VERSION 5.8 ;
BUSBITCHARS "[]" ;
DIVIDERCHAR "/" ;
UNITS
    DATABASE MICRONS 1000 ;
END UNITS

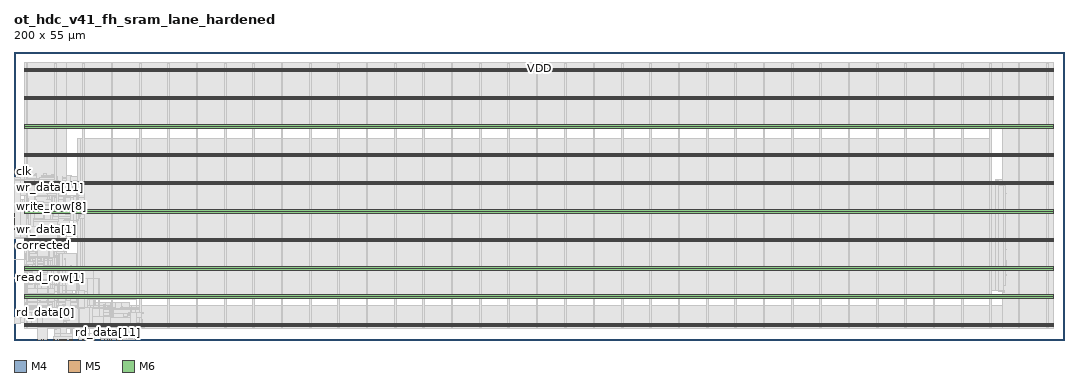
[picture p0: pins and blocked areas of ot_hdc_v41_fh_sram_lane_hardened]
MACRO ot_hdc_v41_fh_sram_lane_hardened
  FOREIGN ot_hdc_v41_fh_sram_lane_hardened 0 0 ;
  CLASS BLOCK ;
  SIZE 200 BY 55 ;
  PIN bank_id[0]
    DIRECTION INPUT ;
    USE SIGNAL ;
    PORT
      LAYER M4 ;
        RECT  0 26.016 0.084 26.04 ;
    END
  END bank_id[0]
  PIN bank_id[1]
    DIRECTION INPUT ;
    USE SIGNAL ;
    PORT
      LAYER M4 ;
        RECT  0 22.176 0.084 22.2 ;
    END
  END bank_id[1]
  PIN bank_id[2]
    DIRECTION INPUT ;
    USE SIGNAL ;
    PORT
      LAYER M4 ;
        RECT  0 22.272 0.084 22.296 ;
    END
  END bank_id[2]
  PIN bank_id[3]
    DIRECTION INPUT ;
    USE SIGNAL ;
    PORT
      LAYER M4 ;
        RECT  0 23.616 0.084 23.64 ;
    END
  END bank_id[3]
  PIN bank_id[4]
    DIRECTION INPUT ;
    USE SIGNAL ;
    PORT
      LAYER M4 ;
        RECT  0 23.712 0.084 23.736 ;
    END
  END bank_id[4]
  PIN bank_id[5]
    DIRECTION INPUT ;
    USE SIGNAL ;
    PORT
      LAYER M4 ;
        RECT  0 24.96 0.084 24.984 ;
    END
  END bank_id[5]
  PIN clk
    DIRECTION INPUT ;
    USE SIGNAL ;
    PORT
      LAYER M4 ;
        RECT  0 30.528 0.084 30.552 ;
    END
  END clk
  PIN corrected
    DIRECTION OUTPUT ;
    USE SIGNAL ;
    PORT
      LAYER M4 ;
        RECT  0 19.488 0.084 19.512 ;
    END
  END corrected
  PIN poisoned
    DIRECTION OUTPUT ;
    USE SIGNAL ;
    PORT
      LAYER M4 ;
        RECT  0 19.68 0.084 19.704 ;
    END
  END poisoned
  PIN rd_data[0]
    DIRECTION OUTPUT ;
    USE SIGNAL ;
    PORT
      LAYER M4 ;
        RECT  0 3.648 0.084 3.672 ;
    END
  END rd_data[0]
  PIN rd_data[10]
    DIRECTION OUTPUT ;
    USE SIGNAL ;
    PORT
      LAYER M5 ;
        RECT  6.432 0 6.456 0.084 ;
    END
  END rd_data[10]
  PIN rd_data[11]
    DIRECTION OUTPUT ;
    USE SIGNAL ;
    PORT
      LAYER M5 ;
        RECT  17.856 0 17.88 0.084 ;
    END
  END rd_data[11]
  PIN rd_data[12]
    DIRECTION OUTPUT ;
    USE SIGNAL ;
    PORT
      LAYER M5 ;
        RECT  17.184 0 17.208 0.084 ;
    END
  END rd_data[12]
  PIN rd_data[13]
    DIRECTION OUTPUT ;
    USE SIGNAL ;
    PORT
      LAYER M5 ;
        RECT  18.528 0 18.552 0.084 ;
    END
  END rd_data[13]
  PIN rd_data[14]
    DIRECTION OUTPUT ;
    USE SIGNAL ;
    PORT
      LAYER M5 ;
        RECT  18.144 0 18.168 0.084 ;
    END
  END rd_data[14]
  PIN rd_data[15]
    DIRECTION OUTPUT ;
    USE SIGNAL ;
    PORT
      LAYER M5 ;
        RECT  20.64 0 20.664 0.084 ;
    END
  END rd_data[15]
  PIN rd_data[16]
    DIRECTION OUTPUT ;
    USE SIGNAL ;
    PORT
      LAYER M5 ;
        RECT  20.736 0 20.76 0.084 ;
    END
  END rd_data[16]
  PIN rd_data[17]
    DIRECTION OUTPUT ;
    USE SIGNAL ;
    PORT
      LAYER M5 ;
        RECT  19.968 0 19.992 0.084 ;
    END
  END rd_data[17]
  PIN rd_data[18]
    DIRECTION OUTPUT ;
    USE SIGNAL ;
    PORT
      LAYER M5 ;
        RECT  19.488 0 19.512 0.084 ;
    END
  END rd_data[18]
  PIN rd_data[19]
    DIRECTION OUTPUT ;
    USE SIGNAL ;
    PORT
      LAYER M5 ;
        RECT  20.16 0 20.184 0.084 ;
    END
  END rd_data[19]
  PIN rd_data[1]
    DIRECTION OUTPUT ;
    USE SIGNAL ;
    PORT
      LAYER M5 ;
        RECT  4.416 0 4.44 0.084 ;
    END
  END rd_data[1]
  PIN rd_data[20]
    DIRECTION OUTPUT ;
    USE SIGNAL ;
    PORT
      LAYER M5 ;
        RECT  20.064 0 20.088 0.084 ;
    END
  END rd_data[20]
  PIN rd_data[21]
    DIRECTION OUTPUT ;
    USE SIGNAL ;
    PORT
      LAYER M5 ;
        RECT  16.512 0 16.536 0.084 ;
    END
  END rd_data[21]
  PIN rd_data[22]
    DIRECTION OUTPUT ;
    USE SIGNAL ;
    PORT
      LAYER M5 ;
        RECT  16.416 0 16.44 0.084 ;
    END
  END rd_data[22]
  PIN rd_data[23]
    DIRECTION OUTPUT ;
    USE SIGNAL ;
    PORT
      LAYER M5 ;
        RECT  13.056 0 13.08 0.084 ;
    END
  END rd_data[23]
  PIN rd_data[24]
    DIRECTION OUTPUT ;
    USE SIGNAL ;
    PORT
      LAYER M5 ;
        RECT  14.304 0 14.328 0.084 ;
    END
  END rd_data[24]
  PIN rd_data[25]
    DIRECTION OUTPUT ;
    USE SIGNAL ;
    PORT
      LAYER M5 ;
        RECT  15.36 0 15.384 0.084 ;
    END
  END rd_data[25]
  PIN rd_data[26]
    DIRECTION OUTPUT ;
    USE SIGNAL ;
    PORT
      LAYER M5 ;
        RECT  12.192 0 12.216 0.084 ;
    END
  END rd_data[26]
  PIN rd_data[27]
    DIRECTION OUTPUT ;
    USE SIGNAL ;
    PORT
      LAYER M5 ;
        RECT  13.152 0 13.176 0.084 ;
    END
  END rd_data[27]
  PIN rd_data[28]
    DIRECTION OUTPUT ;
    USE SIGNAL ;
    PORT
      LAYER M5 ;
        RECT  14.88 0 14.904 0.084 ;
    END
  END rd_data[28]
  PIN rd_data[29]
    DIRECTION OUTPUT ;
    USE SIGNAL ;
    PORT
      LAYER M5 ;
        RECT  10.656 0 10.68 0.084 ;
    END
  END rd_data[29]
  PIN rd_data[2]
    DIRECTION OUTPUT ;
    USE SIGNAL ;
    PORT
      LAYER M4 ;
        RECT  0 3.072 0.084 3.096 ;
    END
  END rd_data[2]
  PIN rd_data[30]
    DIRECTION OUTPUT ;
    USE SIGNAL ;
    PORT
      LAYER M5 ;
        RECT  11.04 0 11.064 0.084 ;
    END
  END rd_data[30]
  PIN rd_data[31]
    DIRECTION OUTPUT ;
    USE SIGNAL ;
    PORT
      LAYER M4 ;
        RECT  0 4.224 0.084 4.248 ;
    END
  END rd_data[31]
  PIN rd_data[3]
    DIRECTION OUTPUT ;
    USE SIGNAL ;
    PORT
      LAYER M5 ;
        RECT  7.488 0 7.512 0.084 ;
    END
  END rd_data[3]
  PIN rd_data[4]
    DIRECTION OUTPUT ;
    USE SIGNAL ;
    PORT
      LAYER M5 ;
        RECT  7.776 0 7.8 0.084 ;
    END
  END rd_data[4]
  PIN rd_data[5]
    DIRECTION OUTPUT ;
    USE SIGNAL ;
    PORT
      LAYER M5 ;
        RECT  8.928 0 8.952 0.084 ;
    END
  END rd_data[5]
  PIN rd_data[6]
    DIRECTION OUTPUT ;
    USE SIGNAL ;
    PORT
      LAYER M5 ;
        RECT  9.888 0 9.912 0.084 ;
    END
  END rd_data[6]
  PIN rd_data[7]
    DIRECTION OUTPUT ;
    USE SIGNAL ;
    PORT
      LAYER M5 ;
        RECT  8.736 0 8.76 0.084 ;
    END
  END rd_data[7]
  PIN rd_data[8]
    DIRECTION OUTPUT ;
    USE SIGNAL ;
    PORT
      LAYER M5 ;
        RECT  5.664 0 5.688 0.084 ;
    END
  END rd_data[8]
  PIN rd_data[9]
    DIRECTION OUTPUT ;
    USE SIGNAL ;
    PORT
      LAYER M5 ;
        RECT  5.184 0 5.208 0.084 ;
    END
  END rd_data[9]
  PIN rd_valid
    DIRECTION OUTPUT ;
    USE SIGNAL ;
    PORT
      LAYER M4 ;
        RECT  0 19.872 0.084 19.896 ;
    END
  END rd_valid
  PIN read_ok
    DIRECTION INPUT ;
    USE SIGNAL ;
    PORT
      LAYER M5 ;
        RECT  8.832 0 8.856 0.084 ;
    END
  END read_ok
  PIN read_row[0]
    DIRECTION INPUT ;
    USE SIGNAL ;
    PORT
      LAYER M5 ;
        RECT  9.024 0 9.048 0.084 ;
    END
  END read_row[0]
  PIN read_row[1]
    DIRECTION INPUT ;
    USE SIGNAL ;
    PORT
      LAYER M4 ;
        RECT  0 11.904 0.084 11.928 ;
    END
  END read_row[1]
  PIN read_row[2]
    DIRECTION INPUT ;
    USE SIGNAL ;
    PORT
      LAYER M5 ;
        RECT  8.352 0 8.376 0.084 ;
    END
  END read_row[2]
  PIN read_row[3]
    DIRECTION INPUT ;
    USE SIGNAL ;
    PORT
      LAYER M4 ;
        RECT  0 15.36 0.084 15.384 ;
    END
  END read_row[3]
  PIN read_row[4]
    DIRECTION INPUT ;
    USE SIGNAL ;
    PORT
      LAYER M5 ;
        RECT  9.12 0 9.144 0.084 ;
    END
  END read_row[4]
  PIN read_row[5]
    DIRECTION INPUT ;
    USE SIGNAL ;
    PORT
      LAYER M5 ;
        RECT  9.216 0 9.24 0.084 ;
    END
  END read_row[5]
  PIN read_row[6]
    DIRECTION INPUT ;
    USE SIGNAL ;
    PORT
      LAYER M5 ;
        RECT  9.312 0 9.336 0.084 ;
    END
  END read_row[6]
  PIN read_row[7]
    DIRECTION INPUT ;
    USE SIGNAL ;
    PORT
      LAYER M5 ;
        RECT  9.408 0 9.432 0.084 ;
    END
  END read_row[7]
  PIN read_row[8]
    DIRECTION INPUT ;
    USE SIGNAL ;
    PORT
      LAYER M5 ;
        RECT  9.504 0 9.528 0.084 ;
    END
  END read_row[8]
  PIN rst_n
    DIRECTION INPUT ;
    USE SIGNAL ;
    PORT
      LAYER M4 ;
        RECT  0 19.584 0.084 19.608 ;
    END
  END rst_n
  PIN wr_committed
    DIRECTION OUTPUT ;
    USE SIGNAL ;
    PORT
      LAYER M4 ;
        RECT  0 19.968 0.084 19.992 ;
    END
  END wr_committed
  PIN wr_data[0]
    DIRECTION INPUT ;
    USE SIGNAL ;
    PORT
      LAYER M4 ;
        RECT  0 24.384 0.084 24.408 ;
    END
  END wr_data[0]
  PIN wr_data[10]
    DIRECTION INPUT ;
    USE SIGNAL ;
    PORT
      LAYER M4 ;
        RECT  0 20.64 0.084 20.664 ;
    END
  END wr_data[10]
  PIN wr_data[11]
    DIRECTION INPUT ;
    USE SIGNAL ;
    PORT
      LAYER M4 ;
        RECT  0 28.992 0.084 29.016 ;
    END
  END wr_data[11]
  PIN wr_data[12]
    DIRECTION INPUT ;
    USE SIGNAL ;
    PORT
      LAYER M4 ;
        RECT  0 23.04 0.084 23.064 ;
    END
  END wr_data[12]
  PIN wr_data[13]
    DIRECTION INPUT ;
    USE SIGNAL ;
    PORT
      LAYER M4 ;
        RECT  0 24 0.084 24.024 ;
    END
  END wr_data[13]
  PIN wr_data[14]
    DIRECTION INPUT ;
    USE SIGNAL ;
    PORT
      LAYER M4 ;
        RECT  0 30.144 0.084 30.168 ;
    END
  END wr_data[14]
  PIN wr_data[15]
    DIRECTION INPUT ;
    USE SIGNAL ;
    PORT
      LAYER M4 ;
        RECT  0 30.72 0.084 30.744 ;
    END
  END wr_data[15]
  PIN wr_data[16]
    DIRECTION INPUT ;
    USE SIGNAL ;
    PORT
      LAYER M4 ;
        RECT  0 30.624 0.084 30.648 ;
    END
  END wr_data[16]
  PIN wr_data[17]
    DIRECTION INPUT ;
    USE SIGNAL ;
    PORT
      LAYER M4 ;
        RECT  0 29.664 0.084 29.688 ;
    END
  END wr_data[17]
  PIN wr_data[18]
    DIRECTION INPUT ;
    USE SIGNAL ;
    PORT
      LAYER M4 ;
        RECT  0 30.912 0.084 30.936 ;
    END
  END wr_data[18]
  PIN wr_data[19]
    DIRECTION INPUT ;
    USE SIGNAL ;
    PORT
      LAYER M4 ;
        RECT  0 30.816 0.084 30.84 ;
    END
  END wr_data[19]
  PIN wr_data[1]
    DIRECTION INPUT ;
    USE SIGNAL ;
    PORT
      LAYER M4 ;
        RECT  0 21.12 0.084 21.144 ;
    END
  END wr_data[1]
  PIN wr_data[20]
    DIRECTION INPUT ;
    USE SIGNAL ;
    PORT
      LAYER M4 ;
        RECT  0 31.008 0.084 31.032 ;
    END
  END wr_data[20]
  PIN wr_data[21]
    DIRECTION INPUT ;
    USE SIGNAL ;
    PORT
      LAYER M4 ;
        RECT  0 30.24 0.084 30.264 ;
    END
  END wr_data[21]
  PIN wr_data[22]
    DIRECTION INPUT ;
    USE SIGNAL ;
    PORT
      LAYER M4 ;
        RECT  0 29.856 0.084 29.88 ;
    END
  END wr_data[22]
  PIN wr_data[23]
    DIRECTION INPUT ;
    USE SIGNAL ;
    PORT
      LAYER M4 ;
        RECT  0 29.76 0.084 29.784 ;
    END
  END wr_data[23]
  PIN wr_data[24]
    DIRECTION INPUT ;
    USE SIGNAL ;
    PORT
      LAYER M4 ;
        RECT  0 28.128 0.084 28.152 ;
    END
  END wr_data[24]
  PIN wr_data[25]
    DIRECTION INPUT ;
    USE SIGNAL ;
    PORT
      LAYER M4 ;
        RECT  0 26.112 0.084 26.136 ;
    END
  END wr_data[25]
  PIN wr_data[26]
    DIRECTION INPUT ;
    USE SIGNAL ;
    PORT
      LAYER M4 ;
        RECT  0 23.808 0.084 23.832 ;
    END
  END wr_data[26]
  PIN wr_data[27]
    DIRECTION INPUT ;
    USE SIGNAL ;
    PORT
      LAYER M4 ;
        RECT  0 29.088 0.084 29.112 ;
    END
  END wr_data[27]
  PIN wr_data[28]
    DIRECTION INPUT ;
    USE SIGNAL ;
    PORT
      LAYER M4 ;
        RECT  0 23.328 0.084 23.352 ;
    END
  END wr_data[28]
  PIN wr_data[29]
    DIRECTION INPUT ;
    USE SIGNAL ;
    PORT
      LAYER M4 ;
        RECT  0 24.768 0.084 24.792 ;
    END
  END wr_data[29]
  PIN wr_data[2]
    DIRECTION INPUT ;
    USE SIGNAL ;
    PORT
      LAYER M4 ;
        RECT  0 21.6 0.084 21.624 ;
    END
  END wr_data[2]
  PIN wr_data[30]
    DIRECTION INPUT ;
    USE SIGNAL ;
    PORT
      LAYER M4 ;
        RECT  0 26.784 0.084 26.808 ;
    END
  END wr_data[30]
  PIN wr_data[31]
    DIRECTION INPUT ;
    USE SIGNAL ;
    PORT
      LAYER M4 ;
        RECT  0 28.32 0.084 28.344 ;
    END
  END wr_data[31]
  PIN wr_data[3]
    DIRECTION INPUT ;
    USE SIGNAL ;
    PORT
      LAYER M4 ;
        RECT  0 23.136 0.084 23.16 ;
    END
  END wr_data[3]
  PIN wr_data[4]
    DIRECTION INPUT ;
    USE SIGNAL ;
    PORT
      LAYER M4 ;
        RECT  0 20.064 0.084 20.088 ;
    END
  END wr_data[4]
  PIN wr_data[5]
    DIRECTION INPUT ;
    USE SIGNAL ;
    PORT
      LAYER M4 ;
        RECT  0 20.256 0.084 20.28 ;
    END
  END wr_data[5]
  PIN wr_data[6]
    DIRECTION INPUT ;
    USE SIGNAL ;
    PORT
      LAYER M4 ;
        RECT  0 20.832 0.084 20.856 ;
    END
  END wr_data[6]
  PIN wr_data[7]
    DIRECTION INPUT ;
    USE SIGNAL ;
    PORT
      LAYER M4 ;
        RECT  0 20.16 0.084 20.184 ;
    END
  END wr_data[7]
  PIN wr_data[8]
    DIRECTION INPUT ;
    USE SIGNAL ;
    PORT
      LAYER M4 ;
        RECT  0 20.544 0.084 20.568 ;
    END
  END wr_data[8]
  PIN wr_data[9]
    DIRECTION INPUT ;
    USE SIGNAL ;
    PORT
      LAYER M4 ;
        RECT  0 20.448 0.084 20.472 ;
    END
  END wr_data[9]
  PIN write_ok
    DIRECTION INPUT ;
    USE SIGNAL ;
    PORT
      LAYER M4 ;
        RECT  0 19.776 0.084 19.8 ;
    END
  END write_ok
  PIN write_row[0]
    DIRECTION INPUT ;
    USE SIGNAL ;
    PORT
      LAYER M4 ;
        RECT  0 23.904 0.084 23.928 ;
    END
  END write_row[0]
  PIN write_row[1]
    DIRECTION INPUT ;
    USE SIGNAL ;
    PORT
      LAYER M4 ;
        RECT  0 24.576 0.084 24.6 ;
    END
  END write_row[1]
  PIN write_row[2]
    DIRECTION INPUT ;
    USE SIGNAL ;
    PORT
      LAYER M4 ;
        RECT  0 27.456 0.084 27.48 ;
    END
  END write_row[2]
  PIN write_row[3]
    DIRECTION INPUT ;
    USE SIGNAL ;
    PORT
      LAYER M4 ;
        RECT  0 20.736 0.084 20.76 ;
    END
  END write_row[3]
  PIN write_row[4]
    DIRECTION INPUT ;
    USE SIGNAL ;
    PORT
      LAYER M4 ;
        RECT  0 20.352 0.084 20.376 ;
    END
  END write_row[4]
  PIN write_row[5]
    DIRECTION INPUT ;
    USE SIGNAL ;
    PORT
      LAYER M4 ;
        RECT  0 22.08 0.084 22.104 ;
    END
  END write_row[5]
  PIN write_row[6]
    DIRECTION INPUT ;
    USE SIGNAL ;
    PORT
      LAYER M4 ;
        RECT  0 22.656 0.084 22.68 ;
    END
  END write_row[6]
  PIN write_row[7]
    DIRECTION INPUT ;
    USE SIGNAL ;
    PORT
      LAYER M4 ;
        RECT  0 26.208 0.084 26.232 ;
    END
  END write_row[7]
  PIN write_row[8]
    DIRECTION INPUT ;
    USE SIGNAL ;
    PORT
      LAYER M4 ;
        RECT  0 25.344 0.084 25.368 ;
    END
  END write_row[8]
  PIN VDD
    DIRECTION INOUT ;
    USE POWER ;
    PORT
      LAYER M6 ;
        RECT  2.052 51.513 197.964 51.801 ;
        RECT  2.052 46.113 197.964 46.401 ;
        RECT  2.052 40.713 197.964 41.001 ;
        RECT  2.052 35.313 197.964 35.601 ;
        RECT  2.052 29.913 197.964 30.201 ;
        RECT  2.052 24.513 197.964 24.801 ;
        RECT  2.052 19.113 197.964 19.401 ;
        RECT  2.052 13.713 197.964 14.001 ;
        RECT  2.052 8.313 197.964 8.601 ;
        RECT  2.052 2.913 197.964 3.201 ;
    END
  END VDD
  PIN VSS
    DIRECTION INOUT ;
    USE GROUND ;
    PORT
      LAYER M6 ;
        RECT  2.052 51.129 197.964 51.417 ;
        RECT  2.052 45.729 197.964 46.017 ;
        RECT  2.052 40.329 197.964 40.617 ;
        RECT  2.052 34.929 197.964 35.217 ;
        RECT  2.052 29.529 197.964 29.817 ;
        RECT  2.052 24.129 197.964 24.417 ;
        RECT  2.052 18.729 197.964 19.017 ;
        RECT  2.052 13.329 197.964 13.617 ;
        RECT  2.052 7.929 197.964 8.217 ;
        RECT  2.052 2.529 197.964 2.817 ;
    END
  END VSS
  OBS
    LAYER LVTN ;
     RECT  4.698 2.7 5.076 2.835 ;
     RECT  6.048 2.7 7.992 2.835 ;
     RECT  9.45 2.7 9.828 2.835 ;
     RECT  10.962 2.7 11.34 2.835 ;
     RECT  12.096 2.7 12.69 2.835 ;
     RECT  14.472 2.7 15.066 2.835 ;
     RECT  15.714 2.7 16.092 2.835 ;
     RECT  16.524 2.7 16.956 2.835 ;
     RECT  17.442 2.7 18.414 2.835 ;
     RECT  19.278 2.7 19.71 2.835 ;
     RECT  20.79 2.7 21.168 2.835 ;
     RECT  22.626 2.7 23.328 2.835 ;
     RECT  23.868 2.7 27 2.835 ;
     RECT  8.046 3.105 8.424 3.24 ;
     RECT  11.934 3.105 12.312 3.24 ;
     RECT  12.96 3.105 14.094 3.24 ;
     RECT  14.958 3.105 15.498 3.24 ;
     RECT  19.494 3.105 19.872 3.24 ;
     RECT  5.076 3.24 6.48 3.375 ;
     RECT  8.046 3.24 9.234 3.375 ;
     RECT  10.8 3.24 11.178 3.375 ;
     RECT  11.61 3.24 11.988 3.375 ;
     RECT  16.146 3.24 19.332 3.375 ;
     RECT  20.628 3.24 22.626 3.375 ;
     RECT  23.274 3.24 24.084 3.375 ;
     RECT  4.698 3.645 5.562 3.78 ;
     RECT  6.966 3.645 8.694 3.78 ;
     RECT  10.098 3.645 10.422 3.78 ;
     RECT  18.198 3.645 20.088 3.78 ;
     RECT  20.466 3.645 21.978 3.78 ;
     RECT  22.14 3.645 23.274 3.78 ;
     RECT  3.672 3.78 5.022 3.915 ;
     RECT  5.292 3.78 5.616 3.915 ;
     RECT  11.07 3.78 11.394 3.915 ;
     RECT  12.474 3.78 15.174 3.915 ;
     RECT  19.656 3.78 20.25 3.915 ;
     RECT  23.76 3.78 27 3.915 ;
     RECT  10.962 4.185 11.61 4.32 ;
     RECT  18.63 4.185 18.954 4.32 ;
     RECT  21.168 4.185 22.086 4.32 ;
     RECT  3.078 4.32 3.78 4.455 ;
     RECT  16.092 4.32 16.74 4.455 ;
     RECT  18.468 4.32 19.44 4.455 ;
     RECT  23.598 4.32 27 4.455 ;
     RECT  4.212 4.725 5.67 4.86 ;
     RECT  9.18 4.725 9.504 4.86 ;
     RECT  3.132 5.265 3.51 5.4 ;
     RECT  14.85 5.4 16.362 5.535 ;
     RECT  3.348 16.605 4.158 16.74 ;
     RECT  2.7 16.74 3.402 16.875 ;
     RECT  4.05 16.74 4.212 16.875 ;
     RECT  4.806 16.74 5.832 16.875 ;
     RECT  4.212 17.145 5.292 17.28 ;
     RECT  2.754 17.28 3.726 17.415 ;
     RECT  5.778 17.28 8.316 17.415 ;
     RECT  4.158 17.685 5.454 17.82 ;
     RECT  3.942 17.82 4.536 17.955 ;
     RECT  5.346 17.82 7.074 17.955 ;
     RECT  7.074 18.225 8.316 18.36 ;
     RECT  3.726 18.36 5.238 18.495 ;
     RECT  4.104 21.06 4.914 21.195 ;
     RECT  5.508 21.06 6.102 21.195 ;
     RECT  4.104 21.465 4.698 21.6 ;
     RECT  2.214 22.005 4.752 22.14 ;
     RECT  5.94 22.005 6.858 22.14 ;
     RECT  5.454 22.14 6.534 22.275 ;
     RECT  4.428 22.545 5.076 22.68 ;
     RECT  4.158 22.68 5.238 22.815 ;
     RECT  5.94 22.68 6.696 22.815 ;
     RECT  4.59 23.085 5.238 23.22 ;
     RECT  5.832 23.085 6.966 23.22 ;
     RECT  2.484 23.22 3.888 23.355 ;
     RECT  2.268 23.625 2.538 23.76 ;
     RECT  5.67 23.76 6.264 23.895 ;
     RECT  5.184 24.3 6.426 24.435 ;
     RECT  2.484 24.705 2.754 24.84 ;
     RECT  5.94 24.705 6.966 24.84 ;
     RECT  5.292 24.84 6.804 24.975 ;
     RECT  4.482 25.245 5.4 25.38 ;
     RECT  6.156 25.245 6.858 25.38 ;
     RECT  3.78 25.38 4.374 25.515 ;
     RECT  2.484 25.785 4.05 25.92 ;
     RECT  6.75 25.785 7.344 25.92 ;
     RECT  3.834 25.92 5.4 26.055 ;
     RECT  3.942 26.46 4.752 26.595 ;
     RECT  7.182 26.46 7.776 26.595 ;
     RECT  3.564 26.865 4.158 27 ;
     RECT  4.482 27 5.076 27.135 ;
     RECT  5.67 27 6.75 27.135 ;
     RECT  7.128 27.405 7.938 27.54 ;
     RECT  4.32 27.54 4.914 27.675 ;
     RECT  5.724 27.54 6.696 27.675 ;
     RECT  6.048 27.945 6.642 28.08 ;
     RECT  7.128 28.08 7.83 28.215 ;
     RECT  5.994 28.485 8.046 28.62 ;
     RECT  5.562 28.62 6.966 28.755 ;
    LAYER LVTP ;
     RECT  4.698 2.835 5.076 2.97 ;
     RECT  6.048 2.835 7.992 2.97 ;
     RECT  9.45 2.835 9.828 2.97 ;
     RECT  10.962 2.835 11.34 2.97 ;
     RECT  12.096 2.835 12.69 2.97 ;
     RECT  14.472 2.835 15.066 2.97 ;
     RECT  15.714 2.835 16.092 2.97 ;
     RECT  16.524 2.835 16.956 2.97 ;
     RECT  17.442 2.835 18.414 2.97 ;
     RECT  19.278 2.835 19.71 2.97 ;
     RECT  20.79 2.835 21.168 2.97 ;
     RECT  22.626 2.835 23.328 2.97 ;
     RECT  23.868 2.835 27 2.97 ;
     RECT  8.046 2.97 8.424 3.105 ;
     RECT  11.934 2.97 12.312 3.105 ;
     RECT  12.96 2.97 14.094 3.105 ;
     RECT  14.958 2.97 15.498 3.105 ;
     RECT  19.494 2.97 19.872 3.105 ;
     RECT  5.076 3.375 6.48 3.51 ;
     RECT  8.046 3.375 9.234 3.51 ;
     RECT  10.8 3.375 11.178 3.51 ;
     RECT  11.61 3.375 11.988 3.51 ;
     RECT  16.146 3.375 19.332 3.51 ;
     RECT  20.628 3.375 22.626 3.51 ;
     RECT  23.274 3.375 24.084 3.51 ;
     RECT  4.698 3.51 5.562 3.645 ;
     RECT  6.966 3.51 8.694 3.645 ;
     RECT  10.098 3.51 10.422 3.645 ;
     RECT  18.198 3.51 20.088 3.645 ;
     RECT  20.466 3.51 21.978 3.645 ;
     RECT  22.14 3.51 23.274 3.645 ;
     RECT  3.672 3.915 5.022 4.05 ;
     RECT  5.292 3.915 5.616 4.05 ;
     RECT  11.07 3.915 11.394 4.05 ;
     RECT  12.474 3.915 15.174 4.05 ;
     RECT  19.656 3.915 20.25 4.05 ;
     RECT  23.76 3.915 27 4.05 ;
     RECT  10.962 4.05 11.61 4.185 ;
     RECT  18.63 4.05 18.954 4.185 ;
     RECT  21.168 4.05 22.086 4.185 ;
     RECT  3.078 4.455 3.78 4.59 ;
     RECT  16.092 4.455 16.74 4.59 ;
     RECT  18.468 4.455 19.44 4.59 ;
     RECT  23.598 4.455 27 4.59 ;
     RECT  4.212 4.59 5.67 4.725 ;
     RECT  9.18 4.59 9.504 4.725 ;
     RECT  3.132 5.13 3.51 5.265 ;
     RECT  14.85 5.535 16.362 5.67 ;
     RECT  3.348 16.47 4.158 16.605 ;
     RECT  2.7 16.875 3.402 17.01 ;
     RECT  4.05 16.875 4.212 17.01 ;
     RECT  4.806 16.875 5.832 17.01 ;
     RECT  4.212 17.01 5.292 17.145 ;
     RECT  2.754 17.415 3.726 17.55 ;
     RECT  5.778 17.415 8.316 17.55 ;
     RECT  4.158 17.55 5.454 17.685 ;
     RECT  3.942 17.955 4.536 18.09 ;
     RECT  5.346 17.955 7.074 18.09 ;
     RECT  7.074 18.09 8.316 18.225 ;
     RECT  3.726 18.495 5.238 18.63 ;
     RECT  4.104 21.195 4.914 21.33 ;
     RECT  5.508 21.195 6.102 21.33 ;
     RECT  4.104 21.33 4.698 21.465 ;
     RECT  2.214 21.87 4.752 22.005 ;
     RECT  5.94 21.87 6.858 22.005 ;
     RECT  5.454 22.275 6.534 22.41 ;
     RECT  4.428 22.41 5.076 22.545 ;
     RECT  4.158 22.815 5.238 22.95 ;
     RECT  5.94 22.815 6.696 22.95 ;
     RECT  4.59 22.95 5.238 23.085 ;
     RECT  5.832 22.95 6.966 23.085 ;
     RECT  2.484 23.355 3.888 23.49 ;
     RECT  2.268 23.49 2.538 23.625 ;
     RECT  5.67 23.895 6.264 24.03 ;
     RECT  5.184 24.435 6.426 24.57 ;
     RECT  2.484 24.57 2.754 24.705 ;
     RECT  5.94 24.57 6.966 24.705 ;
     RECT  5.292 24.975 6.804 25.11 ;
     RECT  4.482 25.11 5.4 25.245 ;
     RECT  6.156 25.11 6.858 25.245 ;
     RECT  3.78 25.515 4.374 25.65 ;
     RECT  2.484 25.65 4.05 25.785 ;
     RECT  6.75 25.65 7.344 25.785 ;
     RECT  3.834 26.055 5.4 26.19 ;
     RECT  3.942 26.595 4.752 26.73 ;
     RECT  7.182 26.595 7.776 26.73 ;
     RECT  3.564 26.73 4.158 26.865 ;
     RECT  4.482 27.135 5.076 27.27 ;
     RECT  5.67 27.135 6.75 27.27 ;
     RECT  7.128 27.27 7.938 27.405 ;
     RECT  4.32 27.675 4.914 27.81 ;
     RECT  5.724 27.675 6.696 27.81 ;
     RECT  6.048 27.81 6.642 27.945 ;
     RECT  7.128 28.215 7.83 28.35 ;
     RECT  5.994 28.35 8.046 28.485 ;
     RECT  5.562 28.755 6.966 28.89 ;
    LAYER RVTN ;
     RECT  2.052 2.16 197.964 2.295 ;
     RECT  2.052 2.565 197.964 2.7 ;
     RECT  2.052 2.7 4.698 2.835 ;
     RECT  5.076 2.7 6.048 2.835 ;
     RECT  7.992 2.7 9.45 2.835 ;
     RECT  9.828 2.7 10.962 2.835 ;
     RECT  11.34 2.7 12.096 2.835 ;
     RECT  12.69 2.7 14.472 2.835 ;
     RECT  15.066 2.7 15.714 2.835 ;
     RECT  16.092 2.7 16.524 2.835 ;
     RECT  16.956 2.7 17.442 2.835 ;
     RECT  18.414 2.7 19.278 2.835 ;
     RECT  19.71 2.7 20.79 2.835 ;
     RECT  21.168 2.7 22.626 2.835 ;
     RECT  23.328 2.7 23.868 2.835 ;
     RECT  27 2.7 197.964 2.835 ;
     RECT  2.052 3.105 8.046 3.24 ;
     RECT  8.424 3.105 11.934 3.24 ;
     RECT  12.312 3.105 12.96 3.24 ;
     RECT  14.094 3.105 14.958 3.24 ;
     RECT  15.498 3.105 19.494 3.24 ;
     RECT  19.872 3.105 197.964 3.24 ;
     RECT  2.052 3.24 5.076 3.375 ;
     RECT  6.48 3.24 8.046 3.375 ;
     RECT  9.234 3.24 10.8 3.375 ;
     RECT  11.178 3.24 11.61 3.375 ;
     RECT  11.988 3.24 16.146 3.375 ;
     RECT  19.332 3.24 20.628 3.375 ;
     RECT  22.626 3.24 23.274 3.375 ;
     RECT  24.084 3.24 197.964 3.375 ;
     RECT  2.052 3.645 4.698 3.78 ;
     RECT  5.562 3.645 6.966 3.78 ;
     RECT  8.694 3.645 10.098 3.78 ;
     RECT  10.422 3.645 18.198 3.78 ;
     RECT  20.088 3.645 20.466 3.78 ;
     RECT  21.978 3.645 22.14 3.78 ;
     RECT  23.274 3.645 197.964 3.78 ;
     RECT  2.052 3.78 3.672 3.915 ;
     RECT  5.022 3.78 5.292 3.915 ;
     RECT  5.616 3.78 11.07 3.915 ;
     RECT  11.394 3.78 12.474 3.915 ;
     RECT  15.174 3.78 19.656 3.915 ;
     RECT  20.25 3.78 23.76 3.915 ;
     RECT  27 3.78 197.964 3.915 ;
     RECT  2.052 4.185 10.962 4.32 ;
     RECT  11.61 4.185 18.63 4.32 ;
     RECT  18.954 4.185 21.168 4.32 ;
     RECT  22.086 4.185 197.964 4.32 ;
     RECT  2.052 4.32 3.078 4.455 ;
     RECT  3.78 4.32 16.092 4.455 ;
     RECT  16.74 4.32 18.468 4.455 ;
     RECT  19.44 4.32 23.598 4.455 ;
     RECT  27 4.32 197.964 4.455 ;
     RECT  2.052 4.725 4.212 4.86 ;
     RECT  5.67 4.725 9.18 4.86 ;
     RECT  9.504 4.725 197.964 4.86 ;
     RECT  2.052 4.86 197.964 4.995 ;
     RECT  2.052 5.265 3.132 5.4 ;
     RECT  3.51 5.265 197.964 5.4 ;
     RECT  2.052 5.4 14.85 5.535 ;
     RECT  16.362 5.4 197.964 5.535 ;
     RECT  2.052 5.805 197.964 6.075 ;
     RECT  2.052 6.345 197.964 6.48 ;
     RECT  2.052 6.48 10.044 6.615 ;
     RECT  188.244 6.48 197.964 6.615 ;
     RECT  2.052 6.885 10.044 7.155 ;
     RECT  188.244 6.885 197.964 7.155 ;
     RECT  2.052 7.425 10.044 7.695 ;
     RECT  188.244 7.425 197.964 7.695 ;
     RECT  2.052 7.965 10.044 8.235 ;
     RECT  188.244 7.965 197.964 8.235 ;
     RECT  2.052 8.505 10.044 8.775 ;
     RECT  188.244 8.505 197.964 8.775 ;
     RECT  2.052 9.045 10.044 9.315 ;
     RECT  188.244 9.045 197.964 9.315 ;
     RECT  2.052 9.585 10.044 9.855 ;
     RECT  188.244 9.585 197.964 9.855 ;
     RECT  2.052 10.125 10.044 10.395 ;
     RECT  188.244 10.125 197.964 10.395 ;
     RECT  2.052 10.665 10.044 10.935 ;
     RECT  188.244 10.665 197.964 10.935 ;
     RECT  2.052 11.205 10.044 11.475 ;
     RECT  188.244 11.205 197.964 11.475 ;
     RECT  2.052 11.745 10.044 12.015 ;
     RECT  188.244 11.745 197.964 12.015 ;
     RECT  2.052 12.285 10.044 12.555 ;
     RECT  188.244 12.285 197.964 12.555 ;
     RECT  2.052 12.825 10.044 13.095 ;
     RECT  188.244 12.825 197.964 13.095 ;
     RECT  2.052 13.365 10.044 13.635 ;
     RECT  188.244 13.365 197.964 13.635 ;
     RECT  2.052 13.905 10.044 14.175 ;
     RECT  188.244 13.905 197.964 14.175 ;
     RECT  2.052 14.445 10.044 14.715 ;
     RECT  188.244 14.445 197.964 14.715 ;
     RECT  2.052 14.985 10.044 15.255 ;
     RECT  188.244 14.985 197.964 15.255 ;
     RECT  2.052 15.525 10.044 15.795 ;
     RECT  188.244 15.525 197.964 15.795 ;
     RECT  2.052 16.065 10.044 16.335 ;
     RECT  188.244 16.065 197.964 16.335 ;
     RECT  2.052 16.605 3.348 16.74 ;
     RECT  4.158 16.605 10.044 16.74 ;
     RECT  2.052 16.74 2.7 16.875 ;
     RECT  3.402 16.74 4.05 16.875 ;
     RECT  4.212 16.74 4.806 16.875 ;
     RECT  5.832 16.74 10.044 16.875 ;
     RECT  188.244 16.605 197.964 16.875 ;
     RECT  2.052 17.145 4.212 17.28 ;
     RECT  5.292 17.145 10.044 17.28 ;
     RECT  2.052 17.28 2.754 17.415 ;
     RECT  3.726 17.28 5.778 17.415 ;
     RECT  8.316 17.28 10.044 17.415 ;
     RECT  188.244 17.145 197.964 17.415 ;
     RECT  2.052 17.685 4.158 17.82 ;
     RECT  5.454 17.685 10.044 17.82 ;
     RECT  2.052 17.82 3.942 17.955 ;
     RECT  4.536 17.82 5.346 17.955 ;
     RECT  7.074 17.82 10.044 17.955 ;
     RECT  188.244 17.685 197.964 17.955 ;
     RECT  2.052 18.225 7.074 18.36 ;
     RECT  8.316 18.225 10.044 18.36 ;
     RECT  2.052 18.36 3.726 18.495 ;
     RECT  5.238 18.36 10.044 18.495 ;
     RECT  188.244 18.225 197.964 18.495 ;
     RECT  2.052 18.765 10.044 19.035 ;
     RECT  188.244 18.765 197.964 19.035 ;
     RECT  2.052 19.305 10.044 19.575 ;
     RECT  188.244 19.305 197.964 19.575 ;
     RECT  2.052 19.845 10.044 20.115 ;
     RECT  188.244 19.845 197.964 20.115 ;
     RECT  2.052 20.385 10.044 20.655 ;
     RECT  188.244 20.385 197.964 20.655 ;
     RECT  2.052 20.925 10.044 21.06 ;
     RECT  2.052 21.06 4.104 21.195 ;
     RECT  4.914 21.06 5.508 21.195 ;
     RECT  6.102 21.06 10.044 21.195 ;
     RECT  188.244 20.925 197.964 21.195 ;
     RECT  2.052 21.465 4.104 21.6 ;
     RECT  4.698 21.465 10.044 21.6 ;
     RECT  2.052 21.6 10.044 21.735 ;
     RECT  188.244 21.465 197.964 21.735 ;
     RECT  2.052 22.005 2.214 22.14 ;
     RECT  4.752 22.005 5.94 22.14 ;
     RECT  6.858 22.005 10.044 22.14 ;
     RECT  2.052 22.14 5.454 22.275 ;
     RECT  6.534 22.14 10.044 22.275 ;
     RECT  188.244 22.005 197.964 22.275 ;
     RECT  2.052 22.545 4.428 22.68 ;
     RECT  5.076 22.545 10.044 22.68 ;
     RECT  2.052 22.68 4.158 22.815 ;
     RECT  5.238 22.68 5.94 22.815 ;
     RECT  6.696 22.68 10.044 22.815 ;
     RECT  188.244 22.545 197.964 22.815 ;
     RECT  2.052 23.085 4.59 23.22 ;
     RECT  5.238 23.085 5.832 23.22 ;
     RECT  6.966 23.085 10.044 23.22 ;
     RECT  2.052 23.22 2.484 23.355 ;
     RECT  3.888 23.22 10.044 23.355 ;
     RECT  188.244 23.085 197.964 23.355 ;
     RECT  2.052 23.625 2.268 23.76 ;
     RECT  2.538 23.625 10.044 23.76 ;
     RECT  2.052 23.76 5.67 23.895 ;
     RECT  6.264 23.76 10.044 23.895 ;
     RECT  188.244 23.625 197.964 23.895 ;
     RECT  2.052 24.165 10.044 24.3 ;
     RECT  2.052 24.3 5.184 24.435 ;
     RECT  6.426 24.3 10.044 24.435 ;
     RECT  188.244 24.165 197.964 24.435 ;
     RECT  2.052 24.705 2.484 24.84 ;
     RECT  2.754 24.705 5.94 24.84 ;
     RECT  6.966 24.705 10.044 24.84 ;
     RECT  2.052 24.84 5.292 24.975 ;
     RECT  6.804 24.84 10.044 24.975 ;
     RECT  188.244 24.705 197.964 24.975 ;
     RECT  2.052 25.245 4.482 25.38 ;
     RECT  5.4 25.245 6.156 25.38 ;
     RECT  6.858 25.245 10.044 25.38 ;
     RECT  2.052 25.38 3.78 25.515 ;
     RECT  4.374 25.38 10.044 25.515 ;
     RECT  188.244 25.245 197.964 25.515 ;
     RECT  2.052 25.785 2.484 25.92 ;
     RECT  4.05 25.785 6.75 25.92 ;
     RECT  7.344 25.785 10.044 25.92 ;
     RECT  2.052 25.92 3.834 26.055 ;
     RECT  5.4 25.92 10.044 26.055 ;
     RECT  188.244 25.785 197.964 26.055 ;
     RECT  2.052 26.325 10.044 26.46 ;
     RECT  2.052 26.46 3.942 26.595 ;
     RECT  4.752 26.46 7.182 26.595 ;
     RECT  7.776 26.46 10.044 26.595 ;
     RECT  188.244 26.325 197.964 26.595 ;
     RECT  2.052 26.865 3.564 27 ;
     RECT  4.158 26.865 10.044 27 ;
     RECT  2.052 27 4.482 27.135 ;
     RECT  5.076 27 5.67 27.135 ;
     RECT  6.75 27 10.044 27.135 ;
     RECT  188.244 26.865 197.964 27.135 ;
     RECT  2.052 27.405 7.128 27.54 ;
     RECT  7.938 27.405 10.044 27.54 ;
     RECT  2.052 27.54 4.32 27.675 ;
     RECT  4.914 27.54 5.724 27.675 ;
     RECT  6.696 27.54 10.044 27.675 ;
     RECT  188.244 27.405 197.964 27.675 ;
     RECT  2.052 27.945 6.048 28.08 ;
     RECT  6.642 27.945 10.044 28.08 ;
     RECT  2.052 28.08 7.128 28.215 ;
     RECT  7.83 28.08 10.044 28.215 ;
     RECT  188.244 27.945 197.964 28.215 ;
     RECT  2.052 28.485 5.994 28.62 ;
     RECT  8.046 28.485 10.044 28.62 ;
     RECT  2.052 28.62 5.562 28.755 ;
     RECT  6.966 28.62 10.044 28.755 ;
     RECT  188.244 28.485 197.964 28.755 ;
     RECT  2.052 29.025 10.044 29.295 ;
     RECT  188.244 29.025 197.964 29.295 ;
     RECT  2.052 29.565 10.044 29.835 ;
     RECT  188.244 29.565 197.964 29.835 ;
     RECT  2.052 30.105 10.044 30.375 ;
     RECT  188.244 30.105 197.964 30.375 ;
     RECT  2.052 30.645 10.044 30.915 ;
     RECT  188.244 30.645 197.964 30.915 ;
     RECT  2.052 31.185 10.044 31.455 ;
     RECT  188.244 31.185 197.964 31.455 ;
     RECT  2.052 31.725 10.044 31.995 ;
     RECT  188.244 31.725 197.964 31.995 ;
     RECT  2.052 32.265 10.044 32.535 ;
     RECT  188.244 32.265 197.964 32.535 ;
     RECT  2.052 32.805 10.044 33.075 ;
     RECT  188.244 32.805 197.964 33.075 ;
     RECT  2.052 33.345 10.044 33.615 ;
     RECT  188.244 33.345 197.964 33.615 ;
     RECT  2.052 33.885 10.044 34.155 ;
     RECT  188.244 33.885 197.964 34.155 ;
     RECT  2.052 34.425 10.044 34.695 ;
     RECT  188.244 34.425 197.964 34.695 ;
     RECT  2.052 34.965 10.044 35.235 ;
     RECT  188.244 34.965 197.964 35.235 ;
     RECT  2.052 35.505 10.044 35.775 ;
     RECT  188.244 35.505 197.964 35.775 ;
     RECT  2.052 36.045 10.044 36.315 ;
     RECT  188.244 36.045 197.964 36.315 ;
     RECT  2.052 36.585 10.044 36.855 ;
     RECT  188.244 36.585 197.964 36.855 ;
     RECT  2.052 37.125 10.044 37.395 ;
     RECT  188.244 37.125 197.964 37.395 ;
     RECT  2.052 37.665 10.044 37.935 ;
     RECT  188.244 37.665 197.964 37.935 ;
     RECT  2.052 38.205 10.044 38.475 ;
     RECT  188.244 38.205 197.964 38.475 ;
     RECT  2.052 38.745 10.044 39.015 ;
     RECT  188.244 38.745 197.964 39.015 ;
     RECT  2.052 39.285 10.044 39.555 ;
     RECT  188.244 39.285 197.964 39.555 ;
     RECT  2.052 39.825 10.044 40.095 ;
     RECT  188.244 39.825 197.964 40.095 ;
     RECT  2.052 40.365 10.044 40.5 ;
     RECT  188.244 40.365 197.964 40.5 ;
     RECT  2.052 40.5 197.964 40.635 ;
     RECT  2.052 40.905 197.964 41.175 ;
     RECT  2.052 41.445 197.964 41.715 ;
     RECT  2.052 41.985 197.964 42.255 ;
     RECT  2.052 42.525 197.964 42.795 ;
     RECT  2.052 43.065 197.964 43.335 ;
     RECT  2.052 43.605 197.964 43.875 ;
     RECT  2.052 44.145 197.964 44.415 ;
     RECT  2.052 44.685 197.964 44.955 ;
     RECT  2.052 45.225 197.964 45.495 ;
     RECT  2.052 45.765 197.964 46.035 ;
     RECT  2.052 46.305 197.964 46.575 ;
     RECT  2.052 46.845 197.964 47.115 ;
     RECT  2.052 47.385 197.964 47.655 ;
     RECT  2.052 47.925 197.964 48.195 ;
     RECT  2.052 48.465 197.964 48.735 ;
     RECT  2.052 49.005 197.964 49.275 ;
     RECT  2.052 49.545 197.964 49.815 ;
     RECT  2.052 50.085 197.964 50.355 ;
     RECT  2.052 50.625 197.964 50.895 ;
     RECT  2.052 51.165 197.964 51.435 ;
     RECT  2.052 51.705 197.964 51.975 ;
     RECT  2.052 52.245 197.964 52.515 ;
     RECT  2.052 52.785 197.964 52.92 ;
    LAYER RVTP ;
     RECT  2.052 2.295 197.964 2.565 ;
     RECT  2.052 2.835 4.698 2.97 ;
     RECT  5.076 2.835 6.048 2.97 ;
     RECT  7.992 2.835 9.45 2.97 ;
     RECT  9.828 2.835 10.962 2.97 ;
     RECT  11.34 2.835 12.096 2.97 ;
     RECT  12.69 2.835 14.472 2.97 ;
     RECT  15.066 2.835 15.714 2.97 ;
     RECT  16.092 2.835 16.524 2.97 ;
     RECT  16.956 2.835 17.442 2.97 ;
     RECT  18.414 2.835 19.278 2.97 ;
     RECT  19.71 2.835 20.79 2.97 ;
     RECT  21.168 2.835 22.626 2.97 ;
     RECT  23.328 2.835 23.868 2.97 ;
     RECT  27 2.835 197.964 2.97 ;
     RECT  2.052 2.97 8.046 3.105 ;
     RECT  8.424 2.97 11.934 3.105 ;
     RECT  12.312 2.97 12.96 3.105 ;
     RECT  14.094 2.97 14.958 3.105 ;
     RECT  15.498 2.97 19.494 3.105 ;
     RECT  19.872 2.97 197.964 3.105 ;
     RECT  2.052 3.375 5.076 3.51 ;
     RECT  6.48 3.375 8.046 3.51 ;
     RECT  9.234 3.375 10.8 3.51 ;
     RECT  11.178 3.375 11.61 3.51 ;
     RECT  11.988 3.375 16.146 3.51 ;
     RECT  19.332 3.375 20.628 3.51 ;
     RECT  22.626 3.375 23.274 3.51 ;
     RECT  24.084 3.375 197.964 3.51 ;
     RECT  2.052 3.51 4.698 3.645 ;
     RECT  5.562 3.51 6.966 3.645 ;
     RECT  8.694 3.51 10.098 3.645 ;
     RECT  10.422 3.51 18.198 3.645 ;
     RECT  20.088 3.51 20.466 3.645 ;
     RECT  21.978 3.51 22.14 3.645 ;
     RECT  23.274 3.51 197.964 3.645 ;
     RECT  2.052 3.915 3.672 4.05 ;
     RECT  5.022 3.915 5.292 4.05 ;
     RECT  5.616 3.915 11.07 4.05 ;
     RECT  11.394 3.915 12.474 4.05 ;
     RECT  15.174 3.915 19.656 4.05 ;
     RECT  20.25 3.915 23.76 4.05 ;
     RECT  27 3.915 197.964 4.05 ;
     RECT  2.052 4.05 10.962 4.185 ;
     RECT  11.61 4.05 18.63 4.185 ;
     RECT  18.954 4.05 21.168 4.185 ;
     RECT  22.086 4.05 197.964 4.185 ;
     RECT  2.052 4.455 3.078 4.59 ;
     RECT  3.78 4.455 16.092 4.59 ;
     RECT  16.74 4.455 18.468 4.59 ;
     RECT  19.44 4.455 23.598 4.59 ;
     RECT  27 4.455 197.964 4.59 ;
     RECT  2.052 4.59 4.212 4.725 ;
     RECT  5.67 4.59 9.18 4.725 ;
     RECT  9.504 4.59 197.964 4.725 ;
     RECT  2.052 4.995 197.964 5.13 ;
     RECT  2.052 5.13 3.132 5.265 ;
     RECT  3.51 5.13 197.964 5.265 ;
     RECT  2.052 5.535 14.85 5.67 ;
     RECT  16.362 5.535 197.964 5.67 ;
     RECT  2.052 5.67 197.964 5.805 ;
     RECT  2.052 6.075 197.964 6.345 ;
     RECT  2.052 6.615 10.044 6.885 ;
     RECT  188.244 6.615 197.964 6.885 ;
     RECT  2.052 7.155 10.044 7.425 ;
     RECT  188.244 7.155 197.964 7.425 ;
     RECT  2.052 7.695 10.044 7.965 ;
     RECT  188.244 7.695 197.964 7.965 ;
     RECT  2.052 8.235 10.044 8.505 ;
     RECT  188.244 8.235 197.964 8.505 ;
     RECT  2.052 8.775 10.044 9.045 ;
     RECT  188.244 8.775 197.964 9.045 ;
     RECT  2.052 9.315 10.044 9.585 ;
     RECT  188.244 9.315 197.964 9.585 ;
     RECT  2.052 9.855 10.044 10.125 ;
     RECT  188.244 9.855 197.964 10.125 ;
     RECT  2.052 10.395 10.044 10.665 ;
     RECT  188.244 10.395 197.964 10.665 ;
     RECT  2.052 10.935 10.044 11.205 ;
     RECT  188.244 10.935 197.964 11.205 ;
     RECT  2.052 11.475 10.044 11.745 ;
     RECT  188.244 11.475 197.964 11.745 ;
     RECT  2.052 12.015 10.044 12.285 ;
     RECT  188.244 12.015 197.964 12.285 ;
     RECT  2.052 12.555 10.044 12.825 ;
     RECT  188.244 12.555 197.964 12.825 ;
     RECT  2.052 13.095 10.044 13.365 ;
     RECT  188.244 13.095 197.964 13.365 ;
     RECT  2.052 13.635 10.044 13.905 ;
     RECT  188.244 13.635 197.964 13.905 ;
     RECT  2.052 14.175 10.044 14.445 ;
     RECT  188.244 14.175 197.964 14.445 ;
     RECT  2.052 14.715 10.044 14.985 ;
     RECT  188.244 14.715 197.964 14.985 ;
     RECT  2.052 15.255 10.044 15.525 ;
     RECT  188.244 15.255 197.964 15.525 ;
     RECT  2.052 15.795 10.044 16.065 ;
     RECT  188.244 15.795 197.964 16.065 ;
     RECT  2.052 16.335 10.044 16.47 ;
     RECT  2.052 16.47 3.348 16.605 ;
     RECT  4.158 16.47 10.044 16.605 ;
     RECT  188.244 16.335 197.964 16.605 ;
     RECT  2.052 16.875 2.7 17.01 ;
     RECT  3.402 16.875 4.05 17.01 ;
     RECT  4.212 16.875 4.806 17.01 ;
     RECT  5.832 16.875 10.044 17.01 ;
     RECT  2.052 17.01 4.212 17.145 ;
     RECT  5.292 17.01 10.044 17.145 ;
     RECT  188.244 16.875 197.964 17.145 ;
     RECT  2.052 17.415 2.754 17.55 ;
     RECT  3.726 17.415 5.778 17.55 ;
     RECT  8.316 17.415 10.044 17.55 ;
     RECT  2.052 17.55 4.158 17.685 ;
     RECT  5.454 17.55 10.044 17.685 ;
     RECT  188.244 17.415 197.964 17.685 ;
     RECT  2.052 17.955 3.942 18.09 ;
     RECT  4.536 17.955 5.346 18.09 ;
     RECT  7.074 17.955 10.044 18.09 ;
     RECT  2.052 18.09 7.074 18.225 ;
     RECT  8.316 18.09 10.044 18.225 ;
     RECT  188.244 17.955 197.964 18.225 ;
     RECT  2.052 18.495 3.726 18.63 ;
     RECT  5.238 18.495 10.044 18.63 ;
     RECT  2.052 18.63 10.044 18.765 ;
     RECT  188.244 18.495 197.964 18.765 ;
     RECT  2.052 19.035 10.044 19.305 ;
     RECT  188.244 19.035 197.964 19.305 ;
     RECT  2.052 19.575 10.044 19.845 ;
     RECT  188.244 19.575 197.964 19.845 ;
     RECT  2.052 20.115 10.044 20.385 ;
     RECT  188.244 20.115 197.964 20.385 ;
     RECT  2.052 20.655 10.044 20.925 ;
     RECT  188.244 20.655 197.964 20.925 ;
     RECT  4.914 21.195 5.508 21.33 ;
     RECT  6.102 21.195 10.044 21.33 ;
     RECT  2.052 21.195 4.104 21.465 ;
     RECT  4.698 21.33 10.044 21.465 ;
     RECT  188.244 21.195 197.964 21.465 ;
     RECT  2.052 21.735 10.044 21.87 ;
     RECT  2.052 21.87 2.214 22.005 ;
     RECT  4.752 21.87 5.94 22.005 ;
     RECT  6.858 21.87 10.044 22.005 ;
     RECT  188.244 21.735 197.964 22.005 ;
     RECT  2.052 22.275 5.454 22.41 ;
     RECT  6.534 22.275 10.044 22.41 ;
     RECT  2.052 22.41 4.428 22.545 ;
     RECT  5.076 22.41 10.044 22.545 ;
     RECT  188.244 22.275 197.964 22.545 ;
     RECT  2.052 22.815 4.158 22.95 ;
     RECT  5.238 22.815 5.94 22.95 ;
     RECT  6.696 22.815 10.044 22.95 ;
     RECT  2.052 22.95 4.59 23.085 ;
     RECT  5.238 22.95 5.832 23.085 ;
     RECT  6.966 22.95 10.044 23.085 ;
     RECT  188.244 22.815 197.964 23.085 ;
     RECT  2.052 23.355 2.484 23.49 ;
     RECT  3.888 23.355 10.044 23.49 ;
     RECT  2.052 23.49 2.268 23.625 ;
     RECT  2.538 23.49 10.044 23.625 ;
     RECT  188.244 23.355 197.964 23.625 ;
     RECT  2.052 23.895 5.67 24.03 ;
     RECT  6.264 23.895 10.044 24.03 ;
     RECT  2.052 24.03 10.044 24.165 ;
     RECT  188.244 23.895 197.964 24.165 ;
     RECT  2.052 24.435 5.184 24.57 ;
     RECT  6.426 24.435 10.044 24.57 ;
     RECT  2.052 24.57 2.484 24.705 ;
     RECT  2.754 24.57 5.94 24.705 ;
     RECT  6.966 24.57 10.044 24.705 ;
     RECT  188.244 24.435 197.964 24.705 ;
     RECT  2.052 24.975 5.292 25.11 ;
     RECT  6.804 24.975 10.044 25.11 ;
     RECT  2.052 25.11 4.482 25.245 ;
     RECT  5.4 25.11 6.156 25.245 ;
     RECT  6.858 25.11 10.044 25.245 ;
     RECT  188.244 24.975 197.964 25.245 ;
     RECT  2.052 25.515 3.78 25.65 ;
     RECT  4.374 25.515 10.044 25.65 ;
     RECT  2.052 25.65 2.484 25.785 ;
     RECT  4.05 25.65 6.75 25.785 ;
     RECT  7.344 25.65 10.044 25.785 ;
     RECT  188.244 25.515 197.964 25.785 ;
     RECT  2.052 26.055 3.834 26.19 ;
     RECT  5.4 26.055 10.044 26.19 ;
     RECT  2.052 26.19 10.044 26.325 ;
     RECT  188.244 26.055 197.964 26.325 ;
     RECT  2.052 26.595 3.942 26.73 ;
     RECT  4.752 26.595 7.182 26.73 ;
     RECT  7.776 26.595 10.044 26.73 ;
     RECT  2.052 26.73 3.564 26.865 ;
     RECT  4.158 26.73 10.044 26.865 ;
     RECT  188.244 26.595 197.964 26.865 ;
     RECT  2.052 27.135 4.482 27.27 ;
     RECT  5.076 27.135 5.67 27.27 ;
     RECT  6.75 27.135 10.044 27.27 ;
     RECT  2.052 27.27 7.128 27.405 ;
     RECT  7.938 27.27 10.044 27.405 ;
     RECT  188.244 27.135 197.964 27.405 ;
     RECT  2.052 27.675 4.32 27.81 ;
     RECT  4.914 27.675 5.724 27.81 ;
     RECT  6.696 27.675 10.044 27.81 ;
     RECT  2.052 27.81 6.048 27.945 ;
     RECT  6.642 27.81 10.044 27.945 ;
     RECT  188.244 27.675 197.964 27.945 ;
     RECT  2.052 28.215 7.128 28.35 ;
     RECT  7.83 28.215 10.044 28.35 ;
     RECT  2.052 28.35 5.994 28.485 ;
     RECT  8.046 28.35 10.044 28.485 ;
     RECT  188.244 28.215 197.964 28.485 ;
     RECT  2.052 28.755 5.562 28.89 ;
     RECT  6.966 28.755 10.044 28.89 ;
     RECT  2.052 28.89 10.044 29.025 ;
     RECT  188.244 28.755 197.964 29.025 ;
     RECT  2.052 29.295 10.044 29.565 ;
     RECT  188.244 29.295 197.964 29.565 ;
     RECT  2.052 29.835 10.044 30.105 ;
     RECT  188.244 29.835 197.964 30.105 ;
     RECT  2.052 30.375 10.044 30.645 ;
     RECT  188.244 30.375 197.964 30.645 ;
     RECT  2.052 30.915 10.044 31.185 ;
     RECT  188.244 30.915 197.964 31.185 ;
     RECT  2.052 31.455 10.044 31.725 ;
     RECT  188.244 31.455 197.964 31.725 ;
     RECT  2.052 31.995 10.044 32.265 ;
     RECT  188.244 31.995 197.964 32.265 ;
     RECT  2.052 32.535 10.044 32.805 ;
     RECT  188.244 32.535 197.964 32.805 ;
     RECT  2.052 33.075 10.044 33.345 ;
     RECT  188.244 33.075 197.964 33.345 ;
     RECT  2.052 33.615 10.044 33.885 ;
     RECT  188.244 33.615 197.964 33.885 ;
     RECT  2.052 34.155 10.044 34.425 ;
     RECT  188.244 34.155 197.964 34.425 ;
     RECT  2.052 34.695 10.044 34.965 ;
     RECT  188.244 34.695 197.964 34.965 ;
     RECT  2.052 35.235 10.044 35.505 ;
     RECT  188.244 35.235 197.964 35.505 ;
     RECT  2.052 35.775 10.044 36.045 ;
     RECT  188.244 35.775 197.964 36.045 ;
     RECT  2.052 36.315 10.044 36.585 ;
     RECT  188.244 36.315 197.964 36.585 ;
     RECT  2.052 36.855 10.044 37.125 ;
     RECT  188.244 36.855 197.964 37.125 ;
     RECT  2.052 37.395 10.044 37.665 ;
     RECT  188.244 37.395 197.964 37.665 ;
     RECT  2.052 37.935 10.044 38.205 ;
     RECT  188.244 37.935 197.964 38.205 ;
     RECT  2.052 38.475 10.044 38.745 ;
     RECT  188.244 38.475 197.964 38.745 ;
     RECT  2.052 39.015 10.044 39.285 ;
     RECT  188.244 39.015 197.964 39.285 ;
     RECT  2.052 39.555 10.044 39.825 ;
     RECT  188.244 39.555 197.964 39.825 ;
     RECT  2.052 40.095 10.044 40.365 ;
     RECT  188.244 40.095 197.964 40.365 ;
     RECT  2.052 40.635 197.964 40.905 ;
     RECT  2.052 41.175 197.964 41.445 ;
     RECT  2.052 41.715 197.964 41.985 ;
     RECT  2.052 42.255 197.964 42.525 ;
     RECT  2.052 42.795 197.964 43.065 ;
     RECT  2.052 43.335 197.964 43.605 ;
     RECT  2.052 43.875 197.964 44.145 ;
     RECT  2.052 44.415 197.964 44.685 ;
     RECT  2.052 44.955 197.964 45.225 ;
     RECT  2.052 45.495 197.964 45.765 ;
     RECT  2.052 46.035 197.964 46.305 ;
     RECT  2.052 46.575 197.964 46.845 ;
     RECT  2.052 47.115 197.964 47.385 ;
     RECT  2.052 47.655 197.964 47.925 ;
     RECT  2.052 48.195 197.964 48.465 ;
     RECT  2.052 48.735 197.964 49.005 ;
     RECT  2.052 49.275 197.964 49.545 ;
     RECT  2.052 49.815 197.964 50.085 ;
     RECT  2.052 50.355 197.964 50.625 ;
     RECT  2.052 50.895 197.964 51.165 ;
     RECT  2.052 51.435 197.964 51.705 ;
     RECT  2.052 51.975 197.964 52.245 ;
     RECT  2.052 52.515 197.964 52.785 ;
    LAYER M1 ;
     RECT  2.052 2.151 197.964 6.489 ;
     RECT  12.096 8.64 186.192 38.34 ;
     RECT  2.052 6.489 10.044 40.491 ;
     RECT  188.244 6.489 197.964 40.491 ;
     RECT  2.052 40.491 197.964 52.929 ;
    LAYER M2 ;
     RECT  0.103 19.35 0.139 19.908 ;
     RECT  0.139 19.35 0.383 20.106 ;
     RECT  0.571 31.392 1.075 31.41 ;
     RECT  0.571 30.312 1.111 30.33 ;
     RECT  1.075 31.23 1.111 31.41 ;
     RECT  0.383 19.35 1.147 19.908 ;
     RECT  0.571 24.102 1.147 24.12 ;
     RECT  0.571 26.262 1.147 26.28 ;
     RECT  1.111 30.312 1.147 31.41 ;
     RECT  1.147 19.35 1.651 21.15 ;
     RECT  1.651 19.35 1.687 21.798 ;
     RECT  1.147 23.022 1.687 23.04 ;
     RECT  1.147 23.904 1.687 26.82 ;
     RECT  1.147 3.276 2.052 4.374 ;
     RECT  1.687 19.35 2.052 26.82 ;
     RECT  0.103 27.918 2.052 27.936 ;
     RECT  1.147 28.8 2.052 28.818 ;
     RECT  1.147 29.772 2.052 31.41 ;
     RECT  2.052 2.151 10.044 52.929 ;
     RECT  10.044 2.151 10.067 7.722 ;
     RECT  10.044 12.186 10.067 15.624 ;
     RECT  10.044 8.55 10.139 8.766 ;
     RECT  10.044 21.006 10.247 27.594 ;
     RECT  10.044 9.828 10.283 10.314 ;
     RECT  10.247 21.006 10.283 27.504 ;
     RECT  10.283 21.006 10.535 22.032 ;
     RECT  10.283 10.296 10.795 10.314 ;
     RECT  10.795 10.296 10.823 10.386 ;
     RECT  10.044 11.286 10.859 11.394 ;
     RECT  10.044 28.458 10.859 31.284 ;
     RECT  10.535 21.438 11.363 22.032 ;
     RECT  10.859 28.458 11.363 31.14 ;
     RECT  10.823 10.368 11.803 10.386 ;
     RECT  10.859 11.376 11.803 11.394 ;
     RECT  10.139 8.748 12.096 8.766 ;
     RECT  11.803 10.368 12.096 11.394 ;
     RECT  10.067 12.186 12.096 14.544 ;
     RECT  10.067 15.606 12.096 15.624 ;
     RECT  11.363 22.014 12.096 22.032 ;
     RECT  10.283 22.788 12.096 27.504 ;
     RECT  11.363 28.458 12.096 29.52 ;
     RECT  11.363 30.348 12.096 30.366 ;
     RECT  11.363 31.122 12.096 31.14 ;
     RECT  10.067 2.151 14.323 7.686 ;
     RECT  14.323 2.106 15.367 7.686 ;
     RECT  15.367 2.034 15.503 7.686 ;
     RECT  15.503 2.034 16.151 7.182 ;
     RECT  16.151 2.106 17.447 7.182 ;
     RECT  17.447 2.151 19.363 7.182 ;
     RECT  19.363 2.106 20.543 7.182 ;
     RECT  20.543 2.106 21.983 7.146 ;
     RECT  21.983 2.106 22.307 6.489 ;
     RECT  12.096 8.64 186.192 38.34 ;
     RECT  186.979 9.522 187.015 10.188 ;
     RECT  186.979 19.116 187.015 23.58 ;
     RECT  187.015 9.522 187.411 10.224 ;
     RECT  186.979 11.142 187.411 17.91 ;
     RECT  187.015 18.972 187.411 23.58 ;
     RECT  187.411 9.522 187.447 23.58 ;
     RECT  186.979 24.642 187.447 30.6 ;
     RECT  22.307 2.151 188.244 6.489 ;
     RECT  187.447 9.216 188.244 30.6 ;
     RECT  10.044 40.491 188.244 52.929 ;
     RECT  188.244 2.151 197.964 52.929 ;
    LAYER M3 ;
     RECT  22.248 0.091 22.266 0.139 ;
     RECT  22.248 0.139 22.914 0.571 ;
     RECT  7.668 0.571 7.866 0.619 ;
     RECT  8.784 0.571 8.946 0.619 ;
     RECT  18.828 0.571 18.846 0.619 ;
     RECT  21.852 0.571 22.914 0.667 ;
     RECT  18.828 0.619 19.494 0.907 ;
     RECT  7.668 0.619 8.946 1.147 ;
     RECT  15.228 0.571 15.246 1.147 ;
     RECT  16.488 1.147 16.506 1.243 ;
     RECT  16.452 1.243 16.506 2.029 ;
     RECT  18.828 0.907 20.106 2.101 ;
     RECT  21.384 0.667 22.914 2.101 ;
     RECT  18.828 2.101 22.914 2.143 ;
     RECT  7.668 1.147 9.666 2.191 ;
     RECT  18.507 2.143 22.914 2.191 ;
     RECT  23.907 2.143 23.997 2.191 ;
     RECT  10.692 1.147 10.71 2.263 ;
     RECT  13.107 2.143 13.197 2.263 ;
     RECT  15.228 1.147 15.39 2.263 ;
     RECT  16.128 2.029 16.506 2.263 ;
     RECT  17.424 2.101 17.442 2.263 ;
     RECT  18.507 2.191 23.997 2.263 ;
     RECT  7.668 2.191 9.846 2.299 ;
     RECT  10.692 2.263 11.358 2.299 ;
     RECT  12.204 1.147 12.222 2.299 ;
     RECT  14.328 1.147 14.346 2.299 ;
     RECT  15.228 2.263 23.997 2.335 ;
     RECT  6.084 2.299 6.102 2.347 ;
     RECT  12.96 2.263 13.197 2.347 ;
     RECT  13.932 2.299 14.346 2.347 ;
     RECT  12.96 2.347 14.346 2.371 ;
     RECT  15.084 2.335 23.997 2.371 ;
     RECT  7.668 2.299 12.222 2.395 ;
     RECT  12.96 2.371 23.997 2.395 ;
     RECT  2.307 2.143 2.397 2.413 ;
     RECT  7.668 2.395 23.997 2.413 ;
     RECT  24.84 2.263 24.858 2.413 ;
     RECT  29.307 2.143 29.397 2.413 ;
     RECT  34.707 2.143 34.797 2.413 ;
     RECT  40.107 2.143 40.197 2.413 ;
     RECT  45.507 2.143 45.597 2.413 ;
     RECT  50.907 2.143 50.997 2.413 ;
     RECT  56.307 2.143 56.397 2.413 ;
     RECT  61.707 2.143 61.797 2.413 ;
     RECT  67.107 2.143 67.197 2.413 ;
     RECT  72.507 2.143 72.597 2.413 ;
     RECT  77.907 2.143 77.997 2.413 ;
     RECT  83.307 2.143 83.397 2.413 ;
     RECT  88.707 2.143 88.797 2.413 ;
     RECT  94.107 2.143 94.197 2.413 ;
     RECT  99.507 2.143 99.597 2.413 ;
     RECT  104.907 2.143 104.997 2.413 ;
     RECT  110.307 2.143 110.397 2.413 ;
     RECT  115.707 2.143 115.797 2.413 ;
     RECT  121.107 2.143 121.197 2.413 ;
     RECT  126.507 2.143 126.597 2.413 ;
     RECT  131.907 2.143 131.997 2.413 ;
     RECT  137.307 2.143 137.397 2.413 ;
     RECT  142.707 2.143 142.797 2.413 ;
     RECT  148.107 2.143 148.197 2.413 ;
     RECT  153.507 2.143 153.597 2.413 ;
     RECT  158.907 2.143 158.997 2.413 ;
     RECT  164.307 2.143 164.397 2.413 ;
     RECT  169.707 2.143 169.797 2.413 ;
     RECT  175.107 2.143 175.197 2.413 ;
     RECT  180.507 2.143 180.597 2.413 ;
     RECT  185.907 2.143 185.997 2.413 ;
     RECT  191.307 2.143 191.397 2.413 ;
     RECT  196.707 2.143 196.797 2.413 ;
     RECT  7.668 2.413 24.858 2.461 ;
     RECT  7.596 2.461 24.858 2.489 ;
     RECT  5.724 2.347 6.102 2.533 ;
     RECT  6.84 2.299 6.858 2.533 ;
     RECT  4.572 2.299 4.59 2.605 ;
     RECT  4.572 2.605 4.734 2.641 ;
     RECT  5.724 2.533 6.858 2.641 ;
     RECT  7.596 2.489 24.498 2.641 ;
     RECT  4.572 2.641 24.498 3.163 ;
     RECT  4.428 3.163 24.498 3.181 ;
     RECT  3.996 3.181 24.498 3.415 ;
     RECT  3.708 3.415 24.498 3.569 ;
     RECT  4.824 3.569 24.498 3.605 ;
     RECT  2.307 2.413 2.589 3.847 ;
     RECT  5.112 3.605 24.498 3.875 ;
     RECT  2.307 3.847 2.862 3.991 ;
     RECT  3.708 3.569 4.05 3.991 ;
     RECT  1.152 3.067 1.17 4.379 ;
     RECT  2.307 3.991 4.05 4.495 ;
     RECT  5.112 3.875 6.246 4.495 ;
     RECT  2.307 4.495 6.246 4.657 ;
     RECT  7.056 3.875 24.282 4.657 ;
     RECT  2.307 4.657 24.282 4.829 ;
     RECT  23.076 4.829 24.282 5.035 ;
     RECT  2.307 4.829 22.338 5.071 ;
     RECT  23.076 5.035 24.606 5.189 ;
     RECT  2.268 5.071 22.338 5.737 ;
     RECT  23.076 5.189 24.189 5.737 ;
     RECT  2.268 5.737 24.189 5.801 ;
     RECT  2.268 5.801 19.386 5.999 ;
     RECT  20.16 5.801 24.189 5.999 ;
     RECT  2.268 5.999 13.734 6.029 ;
     RECT  14.544 5.999 19.386 6.077 ;
     RECT  14.544 6.077 19.206 6.143 ;
     RECT  20.268 5.999 24.189 6.143 ;
     RECT  14.544 6.143 19.026 6.179 ;
     RECT  20.268 6.143 20.61 6.179 ;
     RECT  21.42 6.143 24.189 6.179 ;
     RECT  14.544 6.179 16.182 6.221 ;
     RECT  21.456 6.179 24.189 6.227 ;
     RECT  29.307 2.413 29.589 6.227 ;
     RECT  34.707 2.413 34.989 6.227 ;
     RECT  40.107 2.413 40.389 6.227 ;
     RECT  45.507 2.413 45.789 6.227 ;
     RECT  50.907 2.413 51.189 6.227 ;
     RECT  56.307 2.413 56.589 6.227 ;
     RECT  61.707 2.413 61.989 6.227 ;
     RECT  67.107 2.413 67.389 6.227 ;
     RECT  72.507 2.413 72.789 6.227 ;
     RECT  77.907 2.413 78.189 6.227 ;
     RECT  83.307 2.413 83.589 6.227 ;
     RECT  88.707 2.413 88.989 6.227 ;
     RECT  94.107 2.413 94.389 6.227 ;
     RECT  99.507 2.413 99.789 6.227 ;
     RECT  104.907 2.413 105.189 6.227 ;
     RECT  110.307 2.413 110.589 6.227 ;
     RECT  115.707 2.413 115.989 6.227 ;
     RECT  121.107 2.413 121.389 6.227 ;
     RECT  126.507 2.413 126.789 6.227 ;
     RECT  131.907 2.413 132.189 6.227 ;
     RECT  137.307 2.413 137.589 6.227 ;
     RECT  142.707 2.413 142.989 6.227 ;
     RECT  148.107 2.413 148.389 6.227 ;
     RECT  153.507 2.413 153.789 6.227 ;
     RECT  158.907 2.413 159.189 6.227 ;
     RECT  164.307 2.413 164.589 6.227 ;
     RECT  169.707 2.413 169.989 6.227 ;
     RECT  175.107 2.413 175.389 6.227 ;
     RECT  180.507 2.413 180.789 6.227 ;
     RECT  185.907 2.413 186.189 6.227 ;
     RECT  2.268 6.029 13.698 6.269 ;
     RECT  14.544 6.221 15.894 6.269 ;
     RECT  17.136 6.179 19.026 6.269 ;
     RECT  20.34 6.179 20.61 6.269 ;
     RECT  21.456 6.227 23.997 6.269 ;
     RECT  20.52 6.269 20.61 6.377 ;
     RECT  2.268 6.269 13.266 6.449 ;
     RECT  17.892 6.269 18.738 6.449 ;
     RECT  2.268 6.449 13.197 6.497 ;
     RECT  17.892 6.449 18.597 6.497 ;
     RECT  23.364 6.269 23.997 6.497 ;
     RECT  29.307 6.227 29.397 6.497 ;
     RECT  34.707 6.227 34.797 6.497 ;
     RECT  40.107 6.227 40.197 6.497 ;
     RECT  45.507 6.227 45.597 6.497 ;
     RECT  50.907 6.227 50.997 6.497 ;
     RECT  56.307 6.227 56.397 6.497 ;
     RECT  61.707 6.227 61.797 6.497 ;
     RECT  67.107 6.227 67.197 6.497 ;
     RECT  72.507 6.227 72.597 6.497 ;
     RECT  77.907 6.227 77.997 6.497 ;
     RECT  83.307 6.227 83.397 6.497 ;
     RECT  88.707 6.227 88.797 6.497 ;
     RECT  94.107 6.227 94.197 6.497 ;
     RECT  99.507 6.227 99.597 6.497 ;
     RECT  104.907 6.227 104.997 6.497 ;
     RECT  110.307 6.227 110.397 6.497 ;
     RECT  115.707 6.227 115.797 6.497 ;
     RECT  121.107 6.227 121.197 6.497 ;
     RECT  126.507 6.227 126.597 6.497 ;
     RECT  131.907 6.227 131.997 6.497 ;
     RECT  137.307 6.227 137.397 6.497 ;
     RECT  142.707 6.227 142.797 6.497 ;
     RECT  148.107 6.227 148.197 6.497 ;
     RECT  153.507 6.227 153.597 6.497 ;
     RECT  158.907 6.227 158.997 6.497 ;
     RECT  164.307 6.227 164.397 6.497 ;
     RECT  169.707 6.227 169.797 6.497 ;
     RECT  175.107 6.227 175.197 6.497 ;
     RECT  180.507 6.227 180.597 6.497 ;
     RECT  185.907 6.227 185.997 6.497 ;
     RECT  17.892 6.497 18.342 6.557 ;
     RECT  17.136 6.269 17.154 6.719 ;
     RECT  18.324 6.557 18.342 6.881 ;
     RECT  2.268 6.497 12.654 7.079 ;
     RECT  21.96 6.269 21.978 7.151 ;
     RECT  20.52 6.377 20.538 7.187 ;
     RECT  2.307 7.079 12.654 7.259 ;
     RECT  15.48 6.269 15.498 7.691 ;
     RECT  23.364 6.497 23.382 7.709 ;
     RECT  2.307 7.259 11.97 8.509 ;
     RECT  2.232 8.509 11.97 8.64 ;
     RECT  2.232 8.64 186.192 8.771 ;
     RECT  188.424 8.977 188.442 9.085 ;
     RECT  187.452 9.211 187.47 9.355 ;
     RECT  188.424 9.085 188.658 9.437 ;
     RECT  187.452 9.355 187.506 9.517 ;
     RECT  188.424 9.437 188.442 9.533 ;
     RECT  186.984 9.517 187.506 10.205 ;
     RECT  187.02 10.205 187.506 10.301 ;
     RECT  2.232 8.771 11.07 10.625 ;
     RECT  188.748 10.435 188.766 10.831 ;
     RECT  187.416 10.301 187.506 11.128 ;
     RECT  188.748 10.831 188.802 11.281 ;
     RECT  2.268 10.625 11.07 11.371 ;
     RECT  11.808 8.771 186.192 11.371 ;
     RECT  188.64 11.281 188.802 11.399 ;
     RECT  2.268 11.371 186.192 11.435 ;
     RECT  186.984 11.128 187.506 11.549 ;
     RECT  186.984 11.549 187.434 11.645 ;
     RECT  0.108 11.755 0.126 11.933 ;
     RECT  188.784 11.399 188.802 12.217 ;
     RECT  188.748 12.217 188.802 12.317 ;
     RECT  188.784 12.317 188.802 12.361 ;
     RECT  2.307 11.435 186.192 12.413 ;
     RECT  188.784 12.361 188.982 12.413 ;
     RECT  186.984 11.645 187.074 12.451 ;
     RECT  2.307 12.413 10.53 12.901 ;
     RECT  188.784 12.413 188.802 13.297 ;
     RECT  11.412 12.413 186.192 13.373 ;
     RECT  188.748 13.297 188.802 13.373 ;
     RECT  2.268 12.901 10.53 13.441 ;
     RECT  11.916 13.373 186.192 13.565 ;
     RECT  188.784 13.373 188.802 14.141 ;
     RECT  188.82 14.203 188.946 14.243 ;
     RECT  11.952 13.565 186.192 14.299 ;
     RECT  11.844 14.299 186.192 14.341 ;
     RECT  2.268 13.441 10.854 14.369 ;
     RECT  11.772 14.341 186.192 14.381 ;
     RECT  188.82 14.243 188.838 14.405 ;
     RECT  2.307 14.369 10.854 14.477 ;
     RECT  10.8 14.477 10.854 14.635 ;
     RECT  10.8 14.635 10.89 14.717 ;
     RECT  10.872 14.717 10.89 14.765 ;
     RECT  2.307 14.477 10.062 14.981 ;
     RECT  188.748 15.025 188.766 15.163 ;
     RECT  188.748 15.163 188.946 15.215 ;
     RECT  11.916 14.381 186.192 15.355 ;
     RECT  2.307 14.981 9.954 15.449 ;
     RECT  11.376 15.355 186.192 15.629 ;
     RECT  2.307 15.449 9.702 15.719 ;
     RECT  2.307 15.719 9.558 15.871 ;
     RECT  188.748 15.215 188.766 16.295 ;
     RECT  2.268 15.871 9.558 16.529 ;
     RECT  2.307 16.529 9.558 16.951 ;
     RECT  188.784 16.951 188.802 17.077 ;
     RECT  188.748 17.077 188.802 17.176 ;
     RECT  188.748 17.176 188.874 17.275 ;
     RECT  188.748 17.275 188.946 17.375 ;
     RECT  2.307 16.951 9.846 17.645 ;
     RECT  2.307 17.645 8.982 17.879 ;
     RECT  9.828 17.645 9.846 17.879 ;
     RECT  186.984 12.451 187.506 17.915 ;
     RECT  2.307 17.879 8.658 18.031 ;
     RECT  2.268 18.031 8.658 18.077 ;
     RECT  188.748 17.375 188.874 18.121 ;
     RECT  188.676 18.121 188.874 18.269 ;
     RECT  2.304 18.077 8.658 18.608 ;
     RECT  188.748 18.269 188.874 18.619 ;
     RECT  188.748 18.619 188.91 18.689 ;
     RECT  2.304 18.608 7.989 18.841 ;
     RECT  187.416 17.915 187.506 18.967 ;
     RECT  188.748 18.689 188.838 19.037 ;
     RECT  187.02 18.967 187.506 19.099 ;
     RECT  2.196 18.841 7.989 19.345 ;
     RECT  0.108 19.345 0.126 19.579 ;
     RECT  2.196 19.345 8.55 19.777 ;
     RECT  1.728 19.777 8.55 19.921 ;
     RECT  1.728 19.921 9.27 19.949 ;
     RECT  1.728 19.949 4.914 20.047 ;
     RECT  1.188 20.047 4.914 20.075 ;
     RECT  0.108 19.579 0.342 20.083 ;
     RECT  1.188 20.075 4.806 20.155 ;
     RECT  0.108 20.083 0.378 20.189 ;
     RECT  5.724 19.949 9.27 20.191 ;
     RECT  188.748 19.037 188.802 20.251 ;
     RECT  0.108 20.189 0.162 20.285 ;
     RECT  5.724 20.191 9.738 20.353 ;
     RECT  0.144 20.285 0.162 20.429 ;
     RECT  1.152 20.155 4.806 20.573 ;
     RECT  2.307 20.573 4.806 20.615 ;
     RECT  188.748 20.251 188.874 20.695 ;
     RECT  2.307 20.615 3.366 20.759 ;
     RECT  188.676 20.695 188.874 20.765 ;
     RECT  4.248 20.615 4.806 20.965 ;
     RECT  5.724 20.353 9.918 20.965 ;
     RECT  4.248 20.965 9.918 21.001 ;
     RECT  188.712 20.765 188.874 21.019 ;
     RECT  188.712 21.019 188.91 21.119 ;
     RECT  1.152 20.573 1.206 21.155 ;
     RECT  2.307 20.759 3.042 21.505 ;
     RECT  188.712 21.119 188.874 21.631 ;
     RECT  4.248 21.001 10.53 21.931 ;
     RECT  4.14 21.931 10.53 21.937 ;
     RECT  11.34 21.433 11.358 22.009 ;
     RECT  12.096 15.629 186.192 22.009 ;
     RECT  3.996 21.937 10.53 22.013 ;
     RECT  186.984 19.099 187.506 22.013 ;
     RECT  1.656 21.505 3.042 22.109 ;
     RECT  1.692 22.109 3.042 22.171 ;
     RECT  1.692 22.171 3.15 22.441 ;
     RECT  1.692 22.441 3.294 22.685 ;
     RECT  2.307 22.685 3.294 22.739 ;
     RECT  186.984 22.013 187.038 22.783 ;
     RECT  2.307 22.739 3.15 22.919 ;
     RECT  2.307 22.919 3.078 23.009 ;
     RECT  1.152 23.017 1.17 23.069 ;
     RECT  4.14 22.013 10.53 23.089 ;
     RECT  11.34 22.009 186.192 23.089 ;
     RECT  4.14 23.089 186.192 23.179 ;
     RECT  188.676 21.631 188.874 23.453 ;
     RECT  2.307 23.009 2.934 23.459 ;
     RECT  3.888 23.179 186.192 23.549 ;
     RECT  188.676 23.453 188.802 23.549 ;
     RECT  188.748 23.549 188.802 23.645 ;
     RECT  2.307 23.459 2.862 23.665 ;
     RECT  1.692 23.665 2.862 23.741 ;
     RECT  0.576 23.803 0.594 23.899 ;
     RECT  0.576 23.899 1.17 24.125 ;
     RECT  2.307 23.741 2.862 24.205 ;
     RECT  3.708 23.665 3.726 24.205 ;
     RECT  188.784 23.645 188.802 24.331 ;
     RECT  2.307 24.205 3.726 24.359 ;
     RECT  188.784 24.331 188.91 24.413 ;
     RECT  4.572 23.549 186.192 24.469 ;
     RECT  188.784 24.413 188.874 24.475 ;
     RECT  3.96 24.469 186.192 24.509 ;
     RECT  3.996 24.509 186.192 24.605 ;
     RECT  188.712 24.475 188.874 24.605 ;
     RECT  3.996 24.605 9.954 24.629 ;
     RECT  4.14 24.629 9.954 24.701 ;
     RECT  1.152 24.125 1.17 24.745 ;
     RECT  2.307 24.359 2.934 24.745 ;
     RECT  188.748 24.605 188.874 24.809 ;
     RECT  10.8 24.605 186.192 24.893 ;
     RECT  1.152 24.745 2.934 24.989 ;
     RECT  10.836 24.893 186.192 24.989 ;
     RECT  2.307 24.989 2.934 25.133 ;
     RECT  4.14 24.701 9.918 25.483 ;
     RECT  188.748 24.809 188.766 25.531 ;
     RECT  3.6 25.483 9.918 25.627 ;
     RECT  3.6 25.627 10.242 25.723 ;
     RECT  11.376 24.989 186.192 25.723 ;
     RECT  188.712 25.531 188.766 25.915 ;
     RECT  188.712 25.915 188.91 25.979 ;
     RECT  1.152 24.989 1.17 26.045 ;
     RECT  186.984 22.783 187.506 26.123 ;
     RECT  3.6 25.723 186.192 26.237 ;
     RECT  0.576 26.107 0.594 26.285 ;
     RECT  3.6 26.237 10.854 26.285 ;
     RECT  188.712 25.979 188.874 26.333 ;
     RECT  1.152 26.779 1.17 26.825 ;
     RECT  186.984 26.123 187.002 26.875 ;
     RECT  2.307 25.133 2.754 26.933 ;
     RECT  3.816 26.285 10.854 27.239 ;
     RECT  11.916 26.237 186.192 27.259 ;
     RECT  188.748 26.333 188.874 27.301 ;
     RECT  3.816 27.239 10.242 27.329 ;
     RECT  11.376 27.259 186.192 27.365 ;
     RECT  11.916 27.365 186.192 27.509 ;
     RECT  188.46 27.301 188.874 27.509 ;
     RECT  3.996 27.329 10.242 27.599 ;
     RECT  188.748 27.509 188.874 27.835 ;
     RECT  188.748 27.835 188.946 27.905 ;
     RECT  188.748 27.905 188.802 27.965 ;
     RECT  2.307 26.933 2.646 28.021 ;
     RECT  2.307 28.021 2.754 28.139 ;
     RECT  0.108 27.913 0.126 28.157 ;
     RECT  2.307 28.139 2.646 28.219 ;
     RECT  3.996 27.599 9.882 28.255 ;
     RECT  3.816 28.255 9.882 28.411 ;
     RECT  11.952 27.509 186.192 28.453 ;
     RECT  188.784 27.965 188.802 28.733 ;
     RECT  3.816 28.411 10.242 28.891 ;
     RECT  11.412 28.453 186.192 28.891 ;
     RECT  2.304 28.219 2.646 28.957 ;
     RECT  1.152 28.795 1.17 29.021 ;
     RECT  2.196 28.957 2.646 29.065 ;
     RECT  2.196 29.065 2.754 29.323 ;
     RECT  2.196 29.323 2.862 29.335 ;
     RECT  3.816 28.891 186.192 29.335 ;
     RECT  188.748 29.467 188.766 29.525 ;
     RECT  2.196 29.335 186.192 29.693 ;
     RECT  2.307 29.693 186.192 29.759 ;
     RECT  186.984 26.875 187.506 30.043 ;
     RECT  3.888 29.759 9.918 30.101 ;
     RECT  1.152 29.755 1.17 30.139 ;
     RECT  186.984 30.043 187.542 30.139 ;
     RECT  9.144 30.101 9.918 30.299 ;
     RECT  186.984 30.139 187.578 30.371 ;
     RECT  0.576 30.139 1.17 30.379 ;
     RECT  0.144 30.379 1.17 30.557 ;
     RECT  3.888 30.101 8.262 30.569 ;
     RECT  186.984 30.371 187.002 30.605 ;
     RECT  2.307 29.759 2.898 30.811 ;
     RECT  3.888 30.569 4.194 30.811 ;
     RECT  9.18 30.299 9.918 30.839 ;
     RECT  9.18 30.839 9.846 30.947 ;
     RECT  9.18 30.947 9.666 30.983 ;
     RECT  4.932 30.569 8.262 31.019 ;
     RECT  9.18 30.983 9.198 31.109 ;
     RECT  0.576 30.557 1.17 31.145 ;
     RECT  5.148 31.019 8.262 31.145 ;
     RECT  10.836 29.759 186.192 31.145 ;
     RECT  0.576 31.145 1.098 31.253 ;
     RECT  2.307 30.811 4.194 31.253 ;
     RECT  5.148 31.145 7.989 31.289 ;
     RECT  10.836 31.145 10.854 31.289 ;
     RECT  3.312 31.253 4.194 31.379 ;
     RECT  5.58 31.289 7.989 31.379 ;
     RECT  0.576 31.253 0.594 31.415 ;
     RECT  5.58 31.379 6.174 31.415 ;
     RECT  7.092 31.379 7.989 31.451 ;
     RECT  3.996 31.379 4.194 31.531 ;
     RECT  3.996 31.531 4.338 31.559 ;
     RECT  4.032 31.559 4.338 31.649 ;
     RECT  5.688 31.415 6.174 31.649 ;
     RECT  4.32 31.649 4.338 31.793 ;
     RECT  5.688 31.649 5.706 31.793 ;
     RECT  12.096 31.145 186.192 38.34 ;
     RECT  13.107 40.483 13.197 40.753 ;
     RECT  18.507 40.483 18.597 40.753 ;
     RECT  23.907 40.483 23.997 40.753 ;
     RECT  29.307 40.483 29.397 40.753 ;
     RECT  34.707 40.483 34.797 40.753 ;
     RECT  40.107 40.483 40.197 40.753 ;
     RECT  45.507 40.483 45.597 40.753 ;
     RECT  50.907 40.483 50.997 40.753 ;
     RECT  56.307 40.483 56.397 40.753 ;
     RECT  61.707 40.483 61.797 40.753 ;
     RECT  67.107 40.483 67.197 40.753 ;
     RECT  72.507 40.483 72.597 40.753 ;
     RECT  77.907 40.483 77.997 40.753 ;
     RECT  83.307 40.483 83.397 40.753 ;
     RECT  88.707 40.483 88.797 40.753 ;
     RECT  94.107 40.483 94.197 40.753 ;
     RECT  99.507 40.483 99.597 40.753 ;
     RECT  104.907 40.483 104.997 40.753 ;
     RECT  110.307 40.483 110.397 40.753 ;
     RECT  115.707 40.483 115.797 40.753 ;
     RECT  121.107 40.483 121.197 40.753 ;
     RECT  126.507 40.483 126.597 40.753 ;
     RECT  131.907 40.483 131.997 40.753 ;
     RECT  137.307 40.483 137.397 40.753 ;
     RECT  142.707 40.483 142.797 40.753 ;
     RECT  148.107 40.483 148.197 40.753 ;
     RECT  153.507 40.483 153.597 40.753 ;
     RECT  158.907 40.483 158.997 40.753 ;
     RECT  164.307 40.483 164.397 40.753 ;
     RECT  169.707 40.483 169.797 40.753 ;
     RECT  175.107 40.483 175.197 40.753 ;
     RECT  180.507 40.483 180.597 40.753 ;
     RECT  185.907 40.483 185.997 40.753 ;
     RECT  2.307 31.253 2.589 52.667 ;
     RECT  7.707 31.451 7.989 52.667 ;
     RECT  13.107 40.753 13.389 52.667 ;
     RECT  18.507 40.753 18.789 52.667 ;
     RECT  23.907 40.753 24.189 52.667 ;
     RECT  29.307 40.753 29.589 52.667 ;
     RECT  34.707 40.753 34.989 52.667 ;
     RECT  40.107 40.753 40.389 52.667 ;
     RECT  45.507 40.753 45.789 52.667 ;
     RECT  50.907 40.753 51.189 52.667 ;
     RECT  56.307 40.753 56.589 52.667 ;
     RECT  61.707 40.753 61.989 52.667 ;
     RECT  67.107 40.753 67.389 52.667 ;
     RECT  72.507 40.753 72.789 52.667 ;
     RECT  77.907 40.753 78.189 52.667 ;
     RECT  83.307 40.753 83.589 52.667 ;
     RECT  88.707 40.753 88.989 52.667 ;
     RECT  94.107 40.753 94.389 52.667 ;
     RECT  99.507 40.753 99.789 52.667 ;
     RECT  104.907 40.753 105.189 52.667 ;
     RECT  110.307 40.753 110.589 52.667 ;
     RECT  115.707 40.753 115.989 52.667 ;
     RECT  121.107 40.753 121.389 52.667 ;
     RECT  126.507 40.753 126.789 52.667 ;
     RECT  131.907 40.753 132.189 52.667 ;
     RECT  137.307 40.753 137.589 52.667 ;
     RECT  142.707 40.753 142.989 52.667 ;
     RECT  148.107 40.753 148.389 52.667 ;
     RECT  153.507 40.753 153.789 52.667 ;
     RECT  158.907 40.753 159.189 52.667 ;
     RECT  164.307 40.753 164.589 52.667 ;
     RECT  169.707 40.753 169.989 52.667 ;
     RECT  175.107 40.753 175.389 52.667 ;
     RECT  180.507 40.753 180.789 52.667 ;
     RECT  185.907 40.753 186.189 52.667 ;
     RECT  191.307 2.413 191.589 52.667 ;
     RECT  196.707 2.413 196.989 52.667 ;
     RECT  2.307 52.667 2.397 52.937 ;
     RECT  7.707 52.667 7.797 52.937 ;
     RECT  13.107 52.667 13.197 52.937 ;
     RECT  18.507 52.667 18.597 52.937 ;
     RECT  23.907 52.667 23.997 52.937 ;
     RECT  29.307 52.667 29.397 52.937 ;
     RECT  34.707 52.667 34.797 52.937 ;
     RECT  40.107 52.667 40.197 52.937 ;
     RECT  45.507 52.667 45.597 52.937 ;
     RECT  50.907 52.667 50.997 52.937 ;
     RECT  56.307 52.667 56.397 52.937 ;
     RECT  61.707 52.667 61.797 52.937 ;
     RECT  67.107 52.667 67.197 52.937 ;
     RECT  72.507 52.667 72.597 52.937 ;
     RECT  77.907 52.667 77.997 52.937 ;
     RECT  83.307 52.667 83.397 52.937 ;
     RECT  88.707 52.667 88.797 52.937 ;
     RECT  94.107 52.667 94.197 52.937 ;
     RECT  99.507 52.667 99.597 52.937 ;
     RECT  104.907 52.667 104.997 52.937 ;
     RECT  110.307 52.667 110.397 52.937 ;
     RECT  115.707 52.667 115.797 52.937 ;
     RECT  121.107 52.667 121.197 52.937 ;
     RECT  126.507 52.667 126.597 52.937 ;
     RECT  131.907 52.667 131.997 52.937 ;
     RECT  137.307 52.667 137.397 52.937 ;
     RECT  142.707 52.667 142.797 52.937 ;
     RECT  148.107 52.667 148.197 52.937 ;
     RECT  153.507 52.667 153.597 52.937 ;
     RECT  158.907 52.667 158.997 52.937 ;
     RECT  164.307 52.667 164.397 52.937 ;
     RECT  169.707 52.667 169.797 52.937 ;
     RECT  175.107 52.667 175.197 52.937 ;
     RECT  180.507 52.667 180.597 52.937 ;
     RECT  185.907 52.667 185.997 52.937 ;
     RECT  191.307 52.667 191.397 52.937 ;
     RECT  196.707 52.667 196.797 52.937 ;
    LAYER M4 ;
     RECT  0.06 11.904 0.097 11.928 ;
     RECT  0.097 11.76 0.137 11.928 ;
     RECT  0.06 3.072 1.181 4.248 ;
     RECT  0.06 19.488 1.181 31.032 ;
     RECT  0.06 15.36 2.257 15.384 ;
     RECT  2.149 18.048 2.293 18.072 ;
     RECT  1.181 19.488 2.293 24.984 ;
     RECT  0.137 11.76 2.3 11.784 ;
     RECT  2.257 15.36 2.3 16.296 ;
     RECT  2.293 18.048 2.3 24.984 ;
     RECT  1.181 26.208 2.3 26.232 ;
     RECT  1.181 27.456 2.3 29.688 ;
     RECT  2.3 2.148 2.404 52.932 ;
     RECT  2.404 2.418 2.596 52.662 ;
     RECT  2.596 21.648 2.867 23.4 ;
     RECT  2.596 28.176 2.867 28.2 ;
     RECT  2.596 29.328 2.873 30.792 ;
     RECT  2.596 24.48 2.945 25.128 ;
     RECT  2.873 30.192 2.963 30.792 ;
     RECT  2.596 12.576 3.017 17.448 ;
     RECT  2.596 18.768 3.017 20.184 ;
     RECT  3.017 16.992 3.125 17.448 ;
     RECT  2.867 21.648 3.161 22.2 ;
     RECT  3.017 12.576 3.197 15.432 ;
     RECT  2.596 3.936 3.443 5.256 ;
     RECT  3.197 13.152 3.557 15.432 ;
     RECT  3.017 18.768 3.685 18.792 ;
     RECT  2.867 23.184 3.692 23.4 ;
     RECT  2.945 24.48 3.692 24.504 ;
     RECT  3.557 13.728 3.737 15.048 ;
     RECT  3.692 23.184 3.779 24.504 ;
     RECT  3.125 17.424 3.805 17.448 ;
     RECT  3.685 18.672 3.805 18.792 ;
     RECT  3.443 3.936 3.875 3.96 ;
     RECT  3.779 23.184 3.917 23.208 ;
     RECT  2.596 9.84 3.925 10.872 ;
     RECT  3.884 26.736 3.971 26.76 ;
     RECT  2.963 30.192 3.973 30.216 ;
     RECT  3.779 24.48 3.989 24.504 ;
     RECT  3.973 30.192 4.019 30.84 ;
     RECT  3.697 20.544 4.021 20.568 ;
     RECT  3.161 21.648 4.06 22.008 ;
     RECT  3.973 28.176 4.061 28.2 ;
     RECT  3.98 25.536 4.067 25.56 ;
     RECT  3.805 17.424 4.165 18.792 ;
     RECT  3.925 9.84 4.169 10.92 ;
     RECT  4.019 30.816 4.205 30.84 ;
     RECT  4.021 20.016 4.237 20.568 ;
     RECT  4.06 21.648 4.237 21.96 ;
     RECT  4.165 16.512 4.301 18.792 ;
     RECT  4.301 16.512 4.348 18.888 ;
     RECT  4.237 20.016 4.381 21.96 ;
     RECT  4.405 2.304 4.417 2.328 ;
     RECT  4.348 16.512 4.457 17.16 ;
     RECT  4.381 19.92 4.547 21.96 ;
     RECT  4.417 2.304 4.601 3.192 ;
     RECT  4.348 18.144 4.637 18.888 ;
     RECT  4.693 23.088 4.78 23.112 ;
     RECT  4.525 7.2 4.813 7.512 ;
     RECT  4.547 19.92 4.817 20.568 ;
     RECT  3.737 13.728 4.885 13.992 ;
     RECT  4.457 16.512 4.931 16.872 ;
     RECT  3.737 14.976 4.957 15.048 ;
     RECT  4.813 7.104 5.105 7.512 ;
     RECT  4.405 4.752 5.173 4.776 ;
     RECT  4.957 14.976 5.173 15.384 ;
     RECT  4.169 9.84 5.245 9.864 ;
     RECT  4.169 10.896 5.245 10.92 ;
     RECT  5.173 4.752 5.285 5.64 ;
     RECT  5.285 5.328 5.353 5.64 ;
     RECT  5.125 18.912 5.429 18.936 ;
     RECT  4.817 19.92 5.429 19.944 ;
     RECT  4.601 2.352 5.461 3.192 ;
     RECT  5.317 4.272 5.461 4.296 ;
     RECT  5.42 25.824 5.509 25.848 ;
     RECT  5.461 22.944 5.545 22.968 ;
     RECT  5.509 25.824 5.557 26.424 ;
     RECT  5.353 5.328 5.569 5.784 ;
     RECT  5.557 25.68 5.596 26.424 ;
     RECT  5.596 25.68 5.644 25.704 ;
     RECT  5.461 2.352 5.653 4.296 ;
     RECT  5.516 17.616 5.653 17.64 ;
     RECT  4.885 13.296 5.677 13.992 ;
     RECT  5.173 14.976 5.677 16.104 ;
     RECT  5.653 2.304 5.699 4.296 ;
     RECT  5.605 21.648 5.701 21.672 ;
     RECT  5.677 13.296 5.717 16.104 ;
     RECT  5.701 21.216 5.788 22.392 ;
     RECT  5.701 25.44 5.789 25.464 ;
     RECT  5.653 17.616 6.035 18.552 ;
     RECT  6.035 17.616 6.092 17.64 ;
     RECT  5.105 7.104 6.109 7.224 ;
     RECT  6.044 29.184 6.131 29.208 ;
     RECT  6.092 17.424 6.179 17.64 ;
     RECT  6.109 24.672 6.277 24.696 ;
     RECT  6.109 7.104 6.329 7.464 ;
     RECT  6.277 24 6.401 24.696 ;
     RECT  5.569 5.328 6.433 5.832 ;
     RECT  6.401 24 6.469 24.36 ;
     RECT  5.699 2.304 6.545 3.384 ;
     RECT  6.469 23.952 6.556 24.36 ;
     RECT  5.245 9.84 6.613 10.92 ;
     RECT  6.505 11.952 6.613 11.976 ;
     RECT  6.181 26.784 6.685 26.808 ;
     RECT  6.649 27.84 6.685 27.864 ;
     RECT  6.556 23.952 6.689 24.024 ;
     RECT  6.685 26.784 6.709 27.864 ;
     RECT  6.433 5.28 6.721 5.832 ;
     RECT  5.788 21.6 6.853 21.768 ;
     RECT  6.853 21.6 6.937 22.824 ;
     RECT  6.613 9.84 7.045 11.976 ;
     RECT  5.717 13.296 7.045 15.048 ;
     RECT  6.541 19.584 7.081 19.608 ;
     RECT  6.179 17.616 7.148 17.64 ;
     RECT  7.081 18.912 7.148 19.608 ;
     RECT  7.148 17.616 7.153 19.608 ;
     RECT  6.709 26.784 7.153 27.912 ;
     RECT  7.153 26.208 7.292 27.912 ;
     RECT  7.045 9.84 7.297 15.048 ;
     RECT  5.717 16.08 7.297 16.104 ;
     RECT  6.721 5.28 7.405 6.696 ;
     RECT  7.153 17.616 7.405 19.656 ;
     RECT  7.405 17.088 7.541 19.656 ;
     RECT  6.937 21.36 7.541 22.824 ;
     RECT  7.369 4.224 7.573 4.248 ;
     RECT  6.689 23.952 7.693 23.976 ;
     RECT  6.545 2.304 7.7 2.904 ;
     RECT  7.573 3.936 7.7 4.248 ;
     RECT  7.405 5.28 7.7 7.368 ;
     RECT  7.297 9.84 7.7 16.104 ;
     RECT  7.541 17.088 7.7 22.824 ;
     RECT  7.693 23.952 7.7 24.504 ;
     RECT  7.292 25.92 7.7 27.912 ;
     RECT  6.716 28.944 7.7 29.16 ;
     RECT  7.7 2.148 7.765 52.932 ;
     RECT  7.765 2.016 7.804 52.932 ;
     RECT  7.804 2.016 7.996 52.662 ;
     RECT  7.996 2.016 8.021 5.928 ;
     RECT  8.021 2.016 8.057 3.48 ;
     RECT  7.996 7.344 8.093 16.488 ;
     RECT  7.996 28.224 8.147 28.632 ;
     RECT  8.057 2.304 8.201 3.48 ;
     RECT  7.996 23.376 8.236 27.24 ;
     RECT  7.996 30.336 8.243 30.36 ;
     RECT  8.201 3.456 8.339 3.48 ;
     RECT  7.477 0.576 8.377 0.6 ;
     RECT  7.996 17.472 8.381 19.656 ;
     RECT  8.236 23.376 8.381 26.808 ;
     RECT  8.093 7.584 8.387 16.488 ;
     RECT  8.147 28.368 8.476 28.632 ;
     RECT  8.381 23.376 8.569 23.4 ;
     RECT  8.381 18.576 8.605 19.656 ;
     RECT  8.605 18.576 8.713 18.6 ;
     RECT  8.387 8.304 8.741 16.488 ;
     RECT  8.381 17.472 8.849 17.496 ;
     RECT  8.377 0.576 8.981 0.648 ;
     RECT  8.021 4.608 9.065 5.928 ;
     RECT  8.981 0.576 9.155 1.176 ;
     RECT  8.741 8.784 9.209 16.488 ;
     RECT  9.155 1.152 9.288 1.176 ;
     RECT  9.065 4.608 9.385 5.352 ;
     RECT  8.201 2.304 9.493 2.328 ;
     RECT  9.277 28.32 9.493 28.344 ;
     RECT  9.313 29.328 9.529 29.352 ;
     RECT  9.313 6.768 9.533 6.792 ;
     RECT  9.349 22.8 9.565 22.824 ;
     RECT  9.493 27.792 9.565 28.344 ;
     RECT  9.529 29.328 9.565 29.592 ;
     RECT  9.565 22.8 9.569 23.112 ;
     RECT  9.565 27.792 9.577 29.592 ;
     RECT  9.288 1.152 9.605 1.224 ;
     RECT  8.381 24.48 9.637 26.808 ;
     RECT  9.569 22.848 9.785 23.112 ;
     RECT  9.637 24.48 9.853 27.096 ;
     RECT  9.493 2.304 9.893 2.424 ;
     RECT  9.884 7.584 9.971 7.608 ;
     RECT  10.316 3.552 10.321 3.576 ;
     RECT  9.385 4.56 10.321 5.352 ;
     RECT  10.321 3.552 10.403 5.352 ;
     RECT  10.403 3.744 10.499 5.352 ;
     RECT  10.499 3.888 10.537 5.352 ;
     RECT  9.893 2.304 10.541 2.376 ;
     RECT  10.537 3.888 10.604 5.688 ;
     RECT  9.605 1.152 10.721 1.176 ;
     RECT  10.604 3.888 10.825 5.784 ;
     RECT  9.785 22.848 10.825 22.872 ;
     RECT  9.853 23.904 10.825 27.096 ;
     RECT  9.577 28.32 10.825 29.592 ;
     RECT  10.825 28.32 11.221 29.784 ;
     RECT  11.221 28.32 11.293 30.264 ;
     RECT  10.825 22.848 11.365 27.096 ;
     RECT  11.365 22.848 11.893 27.288 ;
     RECT  11.293 28.32 11.893 30.36 ;
     RECT  11.893 22.848 11.948 30.36 ;
     RECT  10.825 3.888 11.989 6.024 ;
     RECT  9.209 9.456 11.989 16.488 ;
     RECT  11.989 9.408 12.096 16.488 ;
     RECT  8.605 19.632 12.096 19.656 ;
     RECT  11.948 22.656 12.096 30.36 ;
     RECT  10.541 2.304 12.14 2.328 ;
     RECT  11.989 3.6 12.14 6.024 ;
     RECT  12.096 9.408 12.168 30.36 ;
     RECT  12.149 1.152 12.233 1.176 ;
     RECT  12.14 2.304 12.332 6.024 ;
     RECT  12.168 8.64 12.757 38.34 ;
     RECT  12.332 2.304 13.1 6.072 ;
     RECT  13.1 2.148 13.204 6.492 ;
     RECT  13.1 40.488 13.204 52.932 ;
     RECT  13.204 40.758 13.396 52.662 ;
     RECT  12.949 0.096 13.523 0.12 ;
     RECT  13.204 2.304 13.909 6.492 ;
     RECT  13.909 2.304 13.961 6.552 ;
     RECT  13.961 3.12 14.609 6.552 ;
     RECT  14.273 1.152 14.869 1.176 ;
     RECT  14.869 0.576 15.257 1.176 ;
     RECT  15.257 1.152 15.401 1.176 ;
     RECT  15.829 2.88 16.213 2.904 ;
     RECT  14.609 3.936 16.213 6.552 ;
     RECT  16.397 1.248 16.477 1.272 ;
     RECT  16.477 1.152 16.481 1.272 ;
     RECT  16.481 1.152 16.561 1.176 ;
     RECT  16.213 2.88 17.021 6.552 ;
     RECT  17.021 4.656 17.057 6.552 ;
     RECT  17.057 4.656 17.093 5.544 ;
     RECT  17.093 4.656 17.123 5.352 ;
     RECT  17.021 2.88 17.129 3.432 ;
     RECT  17.057 6.528 17.921 6.552 ;
     RECT  17.173 0.576 18.133 0.6 ;
     RECT  17.123 4.656 18.205 5.304 ;
     RECT  17.129 3.36 18.373 3.432 ;
     RECT  18.205 4.656 18.373 6.492 ;
     RECT  17.845 2.304 18.5 2.328 ;
     RECT  18.373 3.36 18.5 6.492 ;
     RECT  18.133 0.576 18.517 0.648 ;
     RECT  18.5 2.148 18.604 6.492 ;
     RECT  18.5 40.488 18.604 52.932 ;
     RECT  18.604 2.304 18.796 6.222 ;
     RECT  18.604 40.758 18.796 52.662 ;
     RECT  18.517 0.576 18.857 0.936 ;
     RECT  18.796 2.304 18.857 2.328 ;
     RECT  18.796 3.408 18.893 6.12 ;
     RECT  18.893 6.048 19.217 6.12 ;
     RECT  19.217 6.048 19.397 6.072 ;
     RECT  18.857 0.624 19.957 0.936 ;
     RECT  19.957 0.576 20.117 0.936 ;
     RECT  20.117 0.576 20.149 0.696 ;
     RECT  20.149 0.192 20.629 0.696 ;
     RECT  18.893 3.408 20.764 5.064 ;
     RECT  20.053 2.304 20.801 2.328 ;
     RECT  20.764 3.408 20.977 3.432 ;
     RECT  20.629 0.096 21.413 0.696 ;
     RECT  20.764 4.512 21.557 5.064 ;
     RECT  21.557 5.04 21.805 5.064 ;
     RECT  20.977 2.496 21.836 3.432 ;
     RECT  21.413 0.096 21.881 0.6 ;
     RECT  21.836 2.496 21.923 3.864 ;
     RECT  21.805 5.04 22.097 5.16 ;
     RECT  22.097 5.136 22.213 5.16 ;
     RECT  21.881 0.096 22.277 0.216 ;
     RECT  22.213 5.136 22.277 6.024 ;
     RECT  22.277 0.144 22.637 0.216 ;
     RECT  22.277 6 22.637 6.024 ;
     RECT  21.923 2.496 22.781 3.432 ;
     RECT  22.637 0.144 22.925 0.168 ;
     RECT  22.781 3.36 23.209 3.432 ;
     RECT  23.209 3.36 23.353 3.912 ;
     RECT  12.757 7.68 23.393 38.34 ;
     RECT  23.353 3.36 23.9 5.16 ;
     RECT  23.9 2.148 24.004 6.492 ;
     RECT  23.9 40.488 24.004 52.932 ;
     RECT  24.004 2.418 24.196 6.222 ;
     RECT  24.004 40.758 24.196 52.662 ;
     RECT  29.3 2.148 29.404 6.492 ;
     RECT  29.3 40.488 29.404 52.932 ;
     RECT  29.404 2.418 29.596 6.222 ;
     RECT  29.404 40.758 29.596 52.662 ;
     RECT  34.7 2.148 34.804 6.492 ;
     RECT  34.7 40.488 34.804 52.932 ;
     RECT  34.804 2.418 34.996 6.222 ;
     RECT  34.804 40.758 34.996 52.662 ;
     RECT  40.1 2.148 40.204 6.492 ;
     RECT  40.1 40.488 40.204 52.932 ;
     RECT  40.204 2.418 40.396 6.222 ;
     RECT  40.204 40.758 40.396 52.662 ;
     RECT  45.5 2.148 45.604 6.492 ;
     RECT  45.5 40.488 45.604 52.932 ;
     RECT  45.604 2.418 45.796 6.222 ;
     RECT  45.604 40.758 45.796 52.662 ;
     RECT  50.9 2.148 51.004 6.492 ;
     RECT  50.9 40.488 51.004 52.932 ;
     RECT  51.004 2.418 51.196 6.222 ;
     RECT  51.004 40.758 51.196 52.662 ;
     RECT  56.3 2.148 56.404 6.492 ;
     RECT  56.3 40.488 56.404 52.932 ;
     RECT  56.404 2.418 56.596 6.222 ;
     RECT  56.404 40.758 56.596 52.662 ;
     RECT  61.7 2.148 61.804 6.492 ;
     RECT  61.7 40.488 61.804 52.932 ;
     RECT  61.804 2.418 61.996 6.222 ;
     RECT  61.804 40.758 61.996 52.662 ;
     RECT  67.1 2.148 67.204 6.492 ;
     RECT  67.1 40.488 67.204 52.932 ;
     RECT  67.204 2.418 67.396 6.222 ;
     RECT  67.204 40.758 67.396 52.662 ;
     RECT  72.5 2.148 72.604 6.492 ;
     RECT  72.5 40.488 72.604 52.932 ;
     RECT  72.604 2.418 72.796 6.222 ;
     RECT  72.604 40.758 72.796 52.662 ;
     RECT  77.9 2.148 78.004 6.492 ;
     RECT  77.9 40.488 78.004 52.932 ;
     RECT  78.004 2.418 78.196 6.222 ;
     RECT  78.004 40.758 78.196 52.662 ;
     RECT  83.3 2.148 83.404 6.492 ;
     RECT  83.3 40.488 83.404 52.932 ;
     RECT  83.404 2.418 83.596 6.222 ;
     RECT  83.404 40.758 83.596 52.662 ;
     RECT  88.7 2.148 88.804 6.492 ;
     RECT  88.7 40.488 88.804 52.932 ;
     RECT  88.804 2.418 88.996 6.222 ;
     RECT  88.804 40.758 88.996 52.662 ;
     RECT  94.1 2.148 94.204 6.492 ;
     RECT  94.1 40.488 94.204 52.932 ;
     RECT  94.204 2.418 94.396 6.222 ;
     RECT  94.204 40.758 94.396 52.662 ;
     RECT  99.5 2.148 99.604 6.492 ;
     RECT  99.5 40.488 99.604 52.932 ;
     RECT  99.604 2.418 99.796 6.222 ;
     RECT  99.604 40.758 99.796 52.662 ;
     RECT  104.9 2.148 105.004 6.492 ;
     RECT  104.9 40.488 105.004 52.932 ;
     RECT  105.004 2.418 105.196 6.222 ;
     RECT  105.004 40.758 105.196 52.662 ;
     RECT  110.3 2.148 110.404 6.492 ;
     RECT  110.3 40.488 110.404 52.932 ;
     RECT  110.404 2.418 110.596 6.222 ;
     RECT  110.404 40.758 110.596 52.662 ;
     RECT  115.7 2.148 115.804 6.492 ;
     RECT  115.7 40.488 115.804 52.932 ;
     RECT  115.804 2.418 115.996 6.222 ;
     RECT  115.804 40.758 115.996 52.662 ;
     RECT  121.1 2.148 121.204 6.492 ;
     RECT  121.1 40.488 121.204 52.932 ;
     RECT  121.204 2.418 121.396 6.222 ;
     RECT  121.204 40.758 121.396 52.662 ;
     RECT  126.5 2.148 126.604 6.492 ;
     RECT  126.5 40.488 126.604 52.932 ;
     RECT  126.604 2.418 126.796 6.222 ;
     RECT  126.604 40.758 126.796 52.662 ;
     RECT  131.9 2.148 132.004 6.492 ;
     RECT  131.9 40.488 132.004 52.932 ;
     RECT  132.004 2.418 132.196 6.222 ;
     RECT  132.004 40.758 132.196 52.662 ;
     RECT  137.3 2.148 137.404 6.492 ;
     RECT  137.3 40.488 137.404 52.932 ;
     RECT  137.404 2.418 137.596 6.222 ;
     RECT  137.404 40.758 137.596 52.662 ;
     RECT  142.7 2.148 142.804 6.492 ;
     RECT  142.7 40.488 142.804 52.932 ;
     RECT  142.804 2.418 142.996 6.222 ;
     RECT  142.804 40.758 142.996 52.662 ;
     RECT  148.1 2.148 148.204 6.492 ;
     RECT  148.1 40.488 148.204 52.932 ;
     RECT  148.204 2.418 148.396 6.222 ;
     RECT  148.204 40.758 148.396 52.662 ;
     RECT  153.5 2.148 153.604 6.492 ;
     RECT  153.5 40.488 153.604 52.932 ;
     RECT  153.604 2.418 153.796 6.222 ;
     RECT  153.604 40.758 153.796 52.662 ;
     RECT  158.9 2.148 159.004 6.492 ;
     RECT  158.9 40.488 159.004 52.932 ;
     RECT  159.004 2.418 159.196 6.222 ;
     RECT  159.004 40.758 159.196 52.662 ;
     RECT  164.3 2.148 164.404 6.492 ;
     RECT  164.3 40.488 164.404 52.932 ;
     RECT  164.404 2.418 164.596 6.222 ;
     RECT  164.404 40.758 164.596 52.662 ;
     RECT  169.7 2.148 169.804 6.492 ;
     RECT  169.7 40.488 169.804 52.932 ;
     RECT  169.804 2.418 169.996 6.222 ;
     RECT  169.804 40.758 169.996 52.662 ;
     RECT  175.1 2.148 175.204 6.492 ;
     RECT  175.1 40.488 175.204 52.932 ;
     RECT  175.204 2.418 175.396 6.222 ;
     RECT  175.204 40.758 175.396 52.662 ;
     RECT  180.5 2.148 180.604 6.492 ;
     RECT  180.5 40.488 180.604 52.932 ;
     RECT  180.604 2.418 180.796 6.222 ;
     RECT  180.604 40.758 180.796 52.662 ;
     RECT  185.9 2.148 186.004 6.492 ;
     RECT  185.9 40.488 186.004 52.932 ;
     RECT  23.393 8.64 186.12 38.34 ;
     RECT  186.004 2.418 186.196 6.222 ;
     RECT  186.004 40.758 186.196 52.662 ;
     RECT  186.12 9.408 187.013 30.264 ;
     RECT  187.013 9.408 187.589 30.168 ;
     RECT  187.589 9.408 188.453 29.496 ;
     RECT  188.453 9.408 188.669 9.432 ;
     RECT  188.453 10.464 188.777 29.496 ;
     RECT  188.777 10.848 188.813 15.192 ;
     RECT  188.777 16.992 188.813 24.792 ;
     RECT  188.777 25.92 188.813 28.728 ;
     RECT  188.813 17.184 188.849 19.032 ;
     RECT  188.849 17.184 188.885 18.648 ;
     RECT  188.813 20.256 188.885 24.792 ;
     RECT  188.813 25.92 188.885 27.864 ;
     RECT  188.885 18.624 188.921 18.648 ;
     RECT  188.885 21.024 188.921 21.048 ;
     RECT  188.885 24.384 188.921 24.408 ;
     RECT  188.885 25.92 188.921 25.944 ;
     RECT  188.813 14.208 188.957 15.192 ;
     RECT  188.885 17.28 188.957 17.304 ;
     RECT  188.885 27.84 188.957 27.864 ;
     RECT  188.813 12.384 188.993 12.408 ;
     RECT  191.3 2.148 191.404 52.932 ;
     RECT  191.404 2.418 191.596 52.662 ;
     RECT  196.7 2.148 196.804 52.932 ;
     RECT  196.804 2.418 196.996 52.662 ;
    LAYER M5 ;
     RECT  12.192 0.016 13.176 0.085 ;
     RECT  14.304 0.016 15.384 0.085 ;
     RECT  16.416 0.016 20.76 0.179 ;
     RECT  16.416 0.179 20.184 0.227 ;
     RECT  7.488 0.016 11.064 0.611 ;
     RECT  12.192 0.085 15.384 0.611 ;
     RECT  16.416 0.227 20.088 0.611 ;
     RECT  8.832 0.611 11.064 0.659 ;
     RECT  17.856 0.611 20.088 0.707 ;
     RECT  17.856 0.707 18.552 0.947 ;
     RECT  8.928 0.659 11.064 1.187 ;
     RECT  12.192 0.611 14.328 1.187 ;
     RECT  15.36 0.611 15.384 1.187 ;
     RECT  16.416 0.611 16.536 1.187 ;
     RECT  16.416 1.187 16.44 1.283 ;
     RECT  7.776 0.611 7.8 2.137 ;
     RECT  17.856 0.947 17.88 2.137 ;
     RECT  4.416 0.016 6.456 2.339 ;
     RECT  8.928 1.187 9.912 2.339 ;
     RECT  11.04 1.187 11.064 2.339 ;
     RECT  17.856 2.137 18.612 2.339 ;
     RECT  20.064 0.707 20.088 2.339 ;
     RECT  12.96 1.187 13.512 2.351 ;
     RECT  5.184 2.339 5.208 2.387 ;
     RECT  9.504 2.339 9.912 2.387 ;
     RECT  12.336 2.351 13.512 2.387 ;
     RECT  2.292 2.137 2.412 2.407 ;
     RECT  7.692 2.137 7.812 2.407 ;
     RECT  18.492 2.339 18.612 2.407 ;
     RECT  23.892 2.137 24.012 2.407 ;
     RECT  29.292 2.137 29.412 2.407 ;
     RECT  34.692 2.137 34.812 2.407 ;
     RECT  40.092 2.137 40.212 2.407 ;
     RECT  45.492 2.137 45.612 2.407 ;
     RECT  50.892 2.137 51.012 2.407 ;
     RECT  56.292 2.137 56.412 2.407 ;
     RECT  61.692 2.137 61.812 2.407 ;
     RECT  67.092 2.137 67.212 2.407 ;
     RECT  72.492 2.137 72.612 2.407 ;
     RECT  77.892 2.137 78.012 2.407 ;
     RECT  83.292 2.137 83.412 2.407 ;
     RECT  88.692 2.137 88.812 2.407 ;
     RECT  94.092 2.137 94.212 2.407 ;
     RECT  99.492 2.137 99.612 2.407 ;
     RECT  104.892 2.137 105.012 2.407 ;
     RECT  110.292 2.137 110.412 2.407 ;
     RECT  115.692 2.137 115.812 2.407 ;
     RECT  121.092 2.137 121.212 2.407 ;
     RECT  126.492 2.137 126.612 2.407 ;
     RECT  131.892 2.137 132.012 2.407 ;
     RECT  137.292 2.137 137.412 2.407 ;
     RECT  142.692 2.137 142.812 2.407 ;
     RECT  148.092 2.137 148.212 2.407 ;
     RECT  153.492 2.137 153.612 2.407 ;
     RECT  158.892 2.137 159.012 2.407 ;
     RECT  164.292 2.137 164.412 2.407 ;
     RECT  169.692 2.137 169.812 2.407 ;
     RECT  175.092 2.137 175.212 2.407 ;
     RECT  180.492 2.137 180.612 2.407 ;
     RECT  185.892 2.137 186.012 2.407 ;
     RECT  191.292 2.137 191.412 2.407 ;
     RECT  196.692 2.137 196.812 2.407 ;
     RECT  9.504 2.387 9.528 2.435 ;
     RECT  12.336 2.387 13.404 3.109 ;
     RECT  16.992 3.283 17.016 3.371 ;
     RECT  18.492 2.407 18.804 3.397 ;
     RECT  7.692 2.407 8.004 3.411 ;
     RECT  12.192 3.109 13.404 3.445 ;
     RECT  7.692 3.411 8.328 3.499 ;
     RECT  12.192 3.445 13.512 3.551 ;
     RECT  10.368 3.445 10.392 3.587 ;
     RECT  12 3.551 13.512 3.635 ;
     RECT  20.688 3.573 20.712 3.661 ;
     RECT  12.528 3.635 13.512 3.695 ;
     RECT  10.464 3.733 10.488 3.819 ;
     RECT  18.492 3.397 19.128 3.893 ;
     RECT  2.292 2.407 2.604 3.925 ;
     RECT  3.84 3.829 3.864 3.925 ;
     RECT  5.568 3.829 5.592 3.925 ;
     RECT  7.692 3.499 8.004 3.925 ;
     RECT  16.224 3.397 16.968 3.925 ;
     RECT  2.292 3.925 3.864 3.971 ;
     RECT  18.384 3.893 19.848 3.981 ;
     RECT  14.784 3.925 16.968 4.011 ;
     RECT  11.28 3.957 11.448 4.045 ;
     RECT  12.528 3.695 13.704 4.115 ;
     RECT  14.784 4.011 14.808 4.139 ;
     RECT  16.08 4.011 16.968 4.139 ;
     RECT  5.472 3.925 5.592 4.213 ;
     RECT  5.472 4.213 5.688 4.243 ;
     RECT  13.092 4.115 13.704 4.261 ;
     RECT  7.584 3.925 8.004 4.267 ;
     RECT  23.892 2.407 24.204 4.277 ;
     RECT  5.328 4.243 5.688 4.307 ;
     RECT  5.328 4.307 5.352 4.331 ;
     RECT  21.888 3.829 21.912 4.331 ;
     RECT  16.08 4.139 16.248 4.355 ;
     RECT  18.384 3.981 19.512 4.365 ;
     RECT  18.384 4.365 18.936 4.451 ;
     RECT  16.08 4.355 16.104 4.459 ;
     RECT  18.384 4.451 18.804 4.459 ;
     RECT  11.424 4.045 11.448 4.587 ;
     RECT  13.092 4.261 14.28 4.587 ;
     RECT  9.408 4.597 9.432 4.691 ;
     RECT  13.092 4.587 13.656 4.739 ;
     RECT  4.416 4.741 4.44 4.843 ;
     RECT  13.092 4.739 13.404 5.109 ;
     RECT  23.376 4.277 24.204 5.171 ;
     RECT  14.976 5.109 15 5.219 ;
     RECT  12 5.109 13.404 5.227 ;
     RECT  2.292 3.971 3.432 5.291 ;
     RECT  17.088 5.125 17.112 5.363 ;
     RECT  12.048 5.227 13.404 5.701 ;
     RECT  10.656 5.749 10.68 5.867 ;
     RECT  22.224 5.087 22.248 6.035 ;
     RECT  12.048 5.701 13.752 6.037 ;
     RECT  18.492 4.459 18.804 6.037 ;
     RECT  18.492 6.037 18.936 6.123 ;
     RECT  12.048 6.037 13.8 6.191 ;
     RECT  15.12 6.037 15.144 6.191 ;
     RECT  12.048 6.191 15.144 6.275 ;
     RECT  7.692 4.267 8.004 7.541 ;
     RECT  9.936 7.541 9.96 7.629 ;
     RECT  7.692 7.541 8.376 8.293 ;
     RECT  7.692 8.293 8.568 9.251 ;
     RECT  12.048 6.275 13.944 9.333 ;
     RECT  7.692 9.251 8.328 10.293 ;
     RECT  9.888 9.909 9.912 10.347 ;
     RECT  7.692 10.293 8.616 10.381 ;
     RECT  7.692 10.381 8.328 10.539 ;
     RECT  7.692 10.539 8.136 10.643 ;
     RECT  2.292 5.291 2.604 10.645 ;
     RECT  2.292 10.645 3.432 10.707 ;
     RECT  2.292 10.707 3.48 10.789 ;
     RECT  6.288 10.485 6.312 10.795 ;
     RECT  2.292 10.789 3.96 10.883 ;
     RECT  3.936 10.883 3.96 10.931 ;
     RECT  16.176 6.181 16.2 11.691 ;
     RECT  6.672 11.413 6.696 11.765 ;
     RECT  7.692 10.643 8.004 11.765 ;
     RECT  6.672 11.765 8.004 11.947 ;
     RECT  6.768 11.947 8.004 11.987 ;
     RECT  12 9.333 13.944 12.044 ;
     RECT  11.952 12.044 13.944 12.267 ;
     RECT  7.692 11.987 8.004 12.691 ;
     RECT  7.692 12.691 8.328 12.779 ;
     RECT  15.12 6.275 15.144 12.779 ;
     RECT  11.952 12.267 13.404 12.907 ;
     RECT  2.292 10.883 2.604 13.103 ;
     RECT  2.292 13.103 3.528 13.187 ;
     RECT  12 12.907 12.072 13.331 ;
     RECT  7.692 12.779 8.004 14.005 ;
     RECT  7.056 14.005 8.004 14.101 ;
     RECT  10.848 13.957 10.872 14.147 ;
     RECT  7.056 14.101 8.328 14.187 ;
     RECT  5.856 14.005 5.88 14.251 ;
     RECT  7.056 14.187 8.004 14.281 ;
     RECT  2.292 13.187 2.604 14.389 ;
     RECT  3.696 13.717 3.72 14.389 ;
     RECT  2.292 14.389 3.72 14.867 ;
     RECT  6.576 14.831 6.6 14.915 ;
     RECT  12 13.331 12.024 15.253 ;
     RECT  9.696 15.407 9.72 15.491 ;
     RECT  11.856 15.253 12.024 15.683 ;
     RECT  7.692 14.281 8.004 15.781 ;
     RECT  5.568 15.685 5.592 15.787 ;
     RECT  7.692 15.781 8.136 15.925 ;
     RECT  7.692 15.925 8.328 16.019 ;
     RECT  12 15.683 12.024 16.499 ;
     RECT  7.692 16.019 8.004 16.885 ;
     RECT  4.896 16.837 4.92 16.939 ;
     RECT  2.292 14.867 2.856 16.981 ;
     RECT  4.416 17.077 4.44 17.171 ;
     RECT  2.292 16.981 3.096 17.397 ;
     RECT  7.44 16.885 8.004 17.461 ;
     RECT  2.292 17.397 4.296 17.579 ;
     RECT  6.144 17.413 6.168 17.589 ;
     RECT  7.44 17.461 8.568 17.589 ;
     RECT  5.568 17.589 8.568 17.677 ;
     RECT  2.292 17.579 2.604 18.037 ;
     RECT  7.2 17.677 8.568 18.061 ;
     RECT  3.696 17.579 4.296 18.133 ;
     RECT  2.16 18.037 2.604 18.219 ;
     RECT  3.696 18.133 4.584 18.293 ;
     RECT  5.568 17.677 6.024 18.293 ;
     RECT  7.392 18.061 8.568 18.527 ;
     RECT  3.696 18.293 6.024 18.603 ;
     RECT  7.392 18.527 8.664 18.611 ;
     RECT  3.696 18.603 5.16 18.707 ;
     RECT  4.32 18.707 5.16 18.899 ;
     RECT  5.136 18.899 5.16 18.947 ;
     RECT  7.392 18.611 8.568 19.427 ;
     RECT  7.392 19.427 8.136 19.563 ;
     RECT  7.392 19.563 8.004 19.573 ;
     RECT  6.816 19.573 8.004 19.657 ;
     RECT  4.32 19.957 4.344 20.051 ;
     RECT  4.512 21.109 4.536 21.139 ;
     RECT  5.712 21.109 5.736 21.251 ;
     RECT  4.416 21.139 4.536 21.397 ;
     RECT  2.292 18.219 2.604 21.599 ;
     RECT  2.292 21.599 3.096 21.683 ;
     RECT  4.368 21.397 4.536 21.907 ;
     RECT  4.128 21.907 4.536 21.973 ;
     RECT  7.584 19.657 8.004 22.005 ;
     RECT  3.984 21.973 4.536 22.059 ;
     RECT  6.864 22.005 8.004 22.645 ;
     RECT  6.768 22.645 8.004 22.861 ;
     RECT  5.712 22.261 5.736 22.895 ;
     RECT  12 19.621 12.024 22.933 ;
     RECT  5.472 22.895 5.736 22.979 ;
     RECT  12 22.933 12.072 23.029 ;
     RECT  3.984 22.059 4.008 23.077 ;
     RECT  11.856 23.029 12.072 23.113 ;
     RECT  2.292 21.683 2.856 23.157 ;
     RECT  3.984 23.077 4.728 23.157 ;
     RECT  11.904 23.113 12.072 23.157 ;
     RECT  13.092 12.907 13.404 23.157 ;
     RECT  7.692 22.861 8.004 23.327 ;
     RECT  2.292 23.157 4.728 23.403 ;
     RECT  2.292 23.403 3.768 23.411 ;
     RECT  7.692 23.327 8.52 23.411 ;
     RECT  7.692 23.411 8.136 23.565 ;
     RECT  3.744 23.411 3.768 23.915 ;
     RECT  6.288 23.349 6.312 23.932 ;
     RECT  11.904 23.157 13.404 23.987 ;
     RECT  6.288 23.932 6.504 24.035 ;
     RECT  6.48 24.035 6.504 24.371 ;
     RECT  2.292 23.411 2.604 24.853 ;
     RECT  2.292 24.853 2.808 24.979 ;
     RECT  7.692 23.565 8.004 24.979 ;
     RECT  2.292 24.979 2.856 25.067 ;
     RECT  7.692 24.979 8.184 25.067 ;
     RECT  5.568 25.397 5.592 25.429 ;
     RECT  4.032 25.397 4.056 25.571 ;
     RECT  7.692 25.067 8.004 25.653 ;
     RECT  5.568 25.429 5.736 25.707 ;
     RECT  5.568 25.707 5.592 25.715 ;
     RECT  5.472 25.781 5.544 25.869 ;
     RECT  7.344 25.653 8.004 25.955 ;
     RECT  12 23.987 13.404 26.421 ;
     RECT  5.52 25.869 5.544 26.445 ;
     RECT  3.936 26.677 3.96 26.771 ;
     RECT  7.692 25.955 8.004 27.205 ;
     RECT  11.952 26.421 13.404 27.205 ;
     RECT  7.692 27.205 8.184 27.381 ;
     RECT  6.288 26.773 6.312 27.551 ;
     RECT  7.584 27.381 8.184 27.551 ;
     RECT  9.504 25.525 9.528 27.827 ;
     RECT  6.288 27.551 8.184 27.947 ;
     RECT  11.904 27.205 13.404 28.086 ;
     RECT  2.292 25.067 2.604 28.127 ;
     RECT  11.952 28.086 13.404 28.139 ;
     RECT  11.952 28.139 11.976 28.173 ;
     RECT  2.292 28.127 2.856 28.211 ;
     RECT  3.984 28.127 4.008 28.211 ;
     RECT  7.692 27.947 8.184 28.533 ;
     RECT  7.692 28.533 8.424 28.643 ;
     RECT  7.692 28.643 8.136 28.917 ;
     RECT  6.768 28.917 8.136 28.971 ;
     RECT  6.768 28.971 8.004 29.109 ;
     RECT  6.096 29.109 8.004 29.171 ;
     RECT  6.096 29.171 6.12 29.219 ;
     RECT  7.692 29.171 8.004 30.291 ;
     RECT  7.692 30.291 8.232 30.379 ;
     RECT  0.144 30.373 0.168 30.507 ;
     RECT  2.292 28.211 2.604 30.661 ;
     RECT  2.292 30.661 2.952 30.803 ;
     RECT  3.984 30.181 4.008 30.857 ;
     RECT  2.292 30.803 2.604 52.673 ;
     RECT  7.692 30.379 8.004 52.673 ;
     RECT  13.092 28.139 13.404 52.673 ;
     RECT  18.492 6.123 18.804 52.673 ;
     RECT  23.892 5.171 24.204 52.673 ;
     RECT  29.292 2.407 29.604 52.673 ;
     RECT  34.692 2.407 35.004 52.673 ;
     RECT  40.092 2.407 40.404 52.673 ;
     RECT  45.492 2.407 45.804 52.673 ;
     RECT  50.892 2.407 51.204 52.673 ;
     RECT  56.292 2.407 56.604 52.673 ;
     RECT  61.692 2.407 62.004 52.673 ;
     RECT  67.092 2.407 67.404 52.673 ;
     RECT  72.492 2.407 72.804 52.673 ;
     RECT  77.892 2.407 78.204 52.673 ;
     RECT  83.292 2.407 83.604 52.673 ;
     RECT  88.692 2.407 89.004 52.673 ;
     RECT  94.092 2.407 94.404 52.673 ;
     RECT  99.492 2.407 99.804 52.673 ;
     RECT  104.892 2.407 105.204 52.673 ;
     RECT  110.292 2.407 110.604 52.673 ;
     RECT  115.692 2.407 116.004 52.673 ;
     RECT  121.092 2.407 121.404 52.673 ;
     RECT  126.492 2.407 126.804 52.673 ;
     RECT  131.892 2.407 132.204 52.673 ;
     RECT  137.292 2.407 137.604 52.673 ;
     RECT  142.692 2.407 143.004 52.673 ;
     RECT  148.092 2.407 148.404 52.673 ;
     RECT  153.492 2.407 153.804 52.673 ;
     RECT  158.892 2.407 159.204 52.673 ;
     RECT  164.292 2.407 164.604 52.673 ;
     RECT  169.692 2.407 170.004 52.673 ;
     RECT  175.092 2.407 175.404 52.673 ;
     RECT  180.492 2.407 180.804 52.673 ;
     RECT  185.892 2.407 186.204 52.673 ;
     RECT  191.292 2.407 191.604 52.673 ;
     RECT  196.692 2.407 197.004 52.673 ;
     RECT  2.292 52.673 2.412 52.943 ;
     RECT  7.692 52.673 7.812 52.943 ;
     RECT  13.092 52.673 13.212 52.943 ;
     RECT  18.492 52.673 18.612 52.943 ;
     RECT  23.892 52.673 24.012 52.943 ;
     RECT  29.292 52.673 29.412 52.943 ;
     RECT  34.692 52.673 34.812 52.943 ;
     RECT  40.092 52.673 40.212 52.943 ;
     RECT  45.492 52.673 45.612 52.943 ;
     RECT  50.892 52.673 51.012 52.943 ;
     RECT  56.292 52.673 56.412 52.943 ;
     RECT  61.692 52.673 61.812 52.943 ;
     RECT  67.092 52.673 67.212 52.943 ;
     RECT  72.492 52.673 72.612 52.943 ;
     RECT  77.892 52.673 78.012 52.943 ;
     RECT  83.292 52.673 83.412 52.943 ;
     RECT  88.692 52.673 88.812 52.943 ;
     RECT  94.092 52.673 94.212 52.943 ;
     RECT  99.492 52.673 99.612 52.943 ;
     RECT  104.892 52.673 105.012 52.943 ;
     RECT  110.292 52.673 110.412 52.943 ;
     RECT  115.692 52.673 115.812 52.943 ;
     RECT  121.092 52.673 121.212 52.943 ;
     RECT  126.492 52.673 126.612 52.943 ;
     RECT  131.892 52.673 132.012 52.943 ;
     RECT  137.292 52.673 137.412 52.943 ;
     RECT  142.692 52.673 142.812 52.943 ;
     RECT  148.092 52.673 148.212 52.943 ;
     RECT  153.492 52.673 153.612 52.943 ;
     RECT  158.892 52.673 159.012 52.943 ;
     RECT  164.292 52.673 164.412 52.943 ;
     RECT  169.692 52.673 169.812 52.943 ;
     RECT  175.092 52.673 175.212 52.943 ;
     RECT  180.492 52.673 180.612 52.943 ;
     RECT  185.892 52.673 186.012 52.943 ;
     RECT  191.292 52.673 191.412 52.943 ;
     RECT  196.692 52.673 196.812 52.943 ;
    LAYER M6 ;
     RECT  0.133 30.464 2.052 30.496 ;
     RECT  2.052 18.729 2.149 19.401 ;
     RECT  2.052 24.129 2.773 24.801 ;
     RECT  2.773 24.129 2.798 24.928 ;
     RECT  2.798 24.129 2.805 25.056 ;
     RECT  2.052 13.329 2.821 14.001 ;
     RECT  2.805 24.129 2.821 25.504 ;
     RECT  2.149 18.176 2.869 19.401 ;
     RECT  2.821 21.952 3.061 25.504 ;
     RECT  2.869 17.024 3.13 19.401 ;
     RECT  2.052 2.529 3.349 3.201 ;
     RECT  3.349 2.529 3.397 4.32 ;
     RECT  2.821 13.329 3.445 14.432 ;
     RECT  3.445 13.12 3.539 14.432 ;
     RECT  3.061 21.632 3.925 25.504 ;
     RECT  2.052 29.529 3.973 30.496 ;
     RECT  2.821 28.16 4.019 28.192 ;
     RECT  3.539 13.329 4.139 14.432 ;
     RECT  3.925 21.632 4.213 26.72 ;
     RECT  3.13 17.088 4.309 19.401 ;
     RECT  4.213 21.184 4.309 26.72 ;
     RECT  4.309 17.088 4.331 26.72 ;
     RECT  4.331 17.088 4.395 26.4 ;
     RECT  3.397 2.529 4.459 5.28 ;
     RECT  3.973 29.529 4.533 30.816 ;
     RECT  4.533 28.928 4.587 30.816 ;
     RECT  4.085 15.744 4.885 15.776 ;
     RECT  4.395 17.088 4.885 19.401 ;
     RECT  4.459 2.529 5.483 4.832 ;
     RECT  4.395 21.12 5.555 26.4 ;
     RECT  5.555 21.12 5.675 25.824 ;
     RECT  5.675 21.12 5.803 25.696 ;
     RECT  4.139 13.329 5.845 14.001 ;
     RECT  4.587 28.928 6.197 30.201 ;
     RECT  3.426 10.752 6.277 10.784 ;
     RECT  6.277 10.496 6.453 10.784 ;
     RECT  5.845 13.329 6.565 14.24 ;
     RECT  4.885 15.744 6.565 19.401 ;
     RECT  6.565 13.329 6.635 19.401 ;
     RECT  6.453 10.496 6.661 11.808 ;
     RECT  6.197 27.904 6.755 30.201 ;
     RECT  6.661 10.496 6.803 11.936 ;
     RECT  6.635 15.744 6.805 19.401 ;
     RECT  5.803 22.016 6.899 25.696 ;
     RECT  6.803 11.84 6.955 11.936 ;
     RECT  6.955 11.904 7.029 11.936 ;
     RECT  6.635 13.329 7.029 14.24 ;
     RECT  7.029 11.904 7.083 14.24 ;
     RECT  6.899 22.272 7.333 25.696 ;
     RECT  7.333 22.272 7.467 25.888 ;
     RECT  7.083 12.736 7.475 14.24 ;
     RECT  6.805 15.744 7.475 19.616 ;
     RECT  7.475 17.984 7.571 19.616 ;
     RECT  6.805 27.584 7.573 27.616 ;
     RECT  7.573 27.392 8.053 27.616 ;
     RECT  6.755 28.928 8.053 30.201 ;
     RECT  7.571 17.984 8.147 19.552 ;
     RECT  8.053 27.392 8.197 30.201 ;
     RECT  2.052 7.929 8.293 8.601 ;
     RECT  6.803 10.496 8.293 10.528 ;
     RECT  7.475 15.744 8.299 15.968 ;
     RECT  8.293 7.929 8.309 10.528 ;
     RECT  8.309 7.808 8.339 10.528 ;
     RECT  7.475 12.736 8.339 14.176 ;
     RECT  8.299 15.936 8.339 15.968 ;
     RECT  8.339 7.808 8.341 10.336 ;
     RECT  8.341 7.552 8.363 10.336 ;
     RECT  8.363 7.552 8.427 8.601 ;
     RECT  8.197 27.392 8.427 30.368 ;
     RECT  8.427 28.544 8.446 30.201 ;
     RECT  7.467 22.656 8.555 25.888 ;
     RECT  8.147 17.984 8.579 19.401 ;
     RECT  8.579 18.56 8.675 19.401 ;
     RECT  5.483 2.529 9.378 4.448 ;
     RECT  9.685 15.424 9.771 15.456 ;
     RECT  8.363 10.304 9.877 10.336 ;
     RECT  9.378 2.529 9.909 4.64 ;
     RECT  6.453 6.208 9.909 6.24 ;
     RECT  9.877 9.92 9.923 10.336 ;
     RECT  8.427 7.929 9.925 8.601 ;
     RECT  9.923 9.92 9.963 9.952 ;
     RECT  9.925 7.552 10.731 8.601 ;
     RECT  8.555 24.129 11.845 24.801 ;
     RECT  8.339 13.329 11.941 14.001 ;
     RECT  10.731 7.929 11.989 8.601 ;
     RECT  11.941 12.096 11.989 14.001 ;
     RECT  11.845 23.04 11.989 24.801 ;
     RECT  11.941 26.432 12.011 28.128 ;
     RECT  12.011 27.264 12.203 28.128 ;
     RECT  12.203 27.392 12.227 28.128 ;
     RECT  11.989 22.848 12.267 24.801 ;
     RECT  12.227 27.392 12.267 27.808 ;
     RECT  9.909 2.529 12.325 6.24 ;
     RECT  12.325 2.368 12.395 6.24 ;
     RECT  11.989 11.072 12.419 14.001 ;
     RECT  12.419 11.456 12.459 14.001 ;
     RECT  12.267 23.168 12.563 24.801 ;
     RECT  12.267 27.584 12.563 27.808 ;
     RECT  12.563 23.552 12.611 24.801 ;
     RECT  12.563 27.776 12.611 27.808 ;
     RECT  11.989 7.929 13.419 9.376 ;
     RECT  12.395 2.529 14.291 6.24 ;
     RECT  14.291 2.529 15.034 6.112 ;
     RECT  12.459 11.648 15.155 14.001 ;
     RECT  15.155 11.648 16.211 11.68 ;
     RECT  15.034 2.529 18.419 4.448 ;
     RECT  15.034 5.952 18.947 6.112 ;
     RECT  18.419 2.529 22.213 4.32 ;
     RECT  18.947 5.952 22.213 5.984 ;
     RECT  22.213 2.529 22.259 5.984 ;
     RECT  22.259 2.529 23.411 5.152 ;
     RECT  23.411 2.529 197.964 3.201 ;
     RECT  13.419 7.929 197.964 8.601 ;
     RECT  15.155 13.329 197.964 14.001 ;
     RECT  8.675 18.729 197.964 19.401 ;
     RECT  12.611 24.129 197.964 24.801 ;
     RECT  8.446 29.529 197.964 30.201 ;
     RECT  2.052 34.929 197.964 35.601 ;
     RECT  2.052 40.329 197.964 41.001 ;
     RECT  2.052 45.729 197.964 46.401 ;
     RECT  2.052 51.129 197.964 51.801 ;
    LAYER M7 ;
     RECT  9.408 3.445 9.44 3.573 ;
     RECT  12.352 2.357 12.384 3.701 ;
     RECT  9.408 3.573 9.76 3.765 ;
     RECT  12.352 3.701 12.512 4.075 ;
     RECT  9.408 3.765 10.528 4.213 ;
     RECT  16.96 3.317 16.992 4.459 ;
     RECT  8.384 4.213 10.528 4.533 ;
     RECT  8.384 4.533 10.72 4.651 ;
     RECT  5.44 3.957 5.472 4.789 ;
     RECT  4.416 4.789 5.472 4.843 ;
     RECT  14.976 4.085 15.008 5.163 ;
     RECT  12.48 4.075 12.512 5.749 ;
     RECT  12.352 5.749 12.512 5.941 ;
     RECT  12.16 5.941 12.512 6.069 ;
     RECT  12.16 6.069 13.408 6.123 ;
     RECT  8.384 4.651 8.416 7.595 ;
     RECT  9.728 4.651 10.72 7.595 ;
     RECT  12.288 6.123 13.408 9.387 ;
     RECT  8.32 7.797 8.352 9.771 ;
     RECT  9.728 7.595 9.952 9.963 ;
     RECT  4.416 4.843 4.448 10.741 ;
     RECT  12.288 9.387 12.448 11.499 ;
     RECT  6.464 6.197 6.496 11.829 ;
     RECT  6.464 11.829 6.944 11.893 ;
     RECT  12.288 11.499 12.32 12.011 ;
     RECT  3.456 10.741 4.448 13.163 ;
     RECT  6.464 11.893 7.072 14.123 ;
     RECT  6.464 14.123 6.944 14.251 ;
     RECT  6.464 14.251 6.624 14.891 ;
     RECT  9.728 9.963 9.76 15.467 ;
     RECT  4.096 13.163 4.448 15.787 ;
     RECT  4.416 15.787 4.448 15.861 ;
     RECT  6.464 14.891 6.496 15.861 ;
     RECT  8.256 14.133 8.288 15.979 ;
     RECT  2.88 17.013 3.104 17.525 ;
     RECT  4.416 15.861 6.496 17.525 ;
     RECT  2.88 17.525 6.496 17.589 ;
     RECT  2.88 17.589 6.688 18.037 ;
     RECT  2.88 18.037 7.456 18.421 ;
     RECT  2.88 18.421 8.224 18.667 ;
     RECT  3.072 18.667 8.224 21.675 ;
     RECT  3.776 21.675 8.224 22.645 ;
     RECT  3.776 22.645 8.544 22.955 ;
     RECT  12.224 22.837 12.256 23.029 ;
     RECT  3.776 22.955 5.664 23.211 ;
     RECT  7.424 22.955 8.544 23.531 ;
     RECT  3.968 23.211 5.664 25.013 ;
     RECT  8.512 23.531 8.544 25.013 ;
     RECT  2.816 25.013 5.664 25.451 ;
     RECT  2.816 25.451 4.32 25.515 ;
     RECT  5.632 25.451 5.664 25.835 ;
     RECT  8.384 25.013 8.544 25.845 ;
     RECT  8.064 25.845 8.544 25.899 ;
     RECT  11.968 23.029 12.256 26.475 ;
     RECT  3.968 25.515 4.32 26.731 ;
     RECT  12.096 26.475 12.256 27.435 ;
     RECT  12.096 27.435 12.128 27.947 ;
     RECT  8.064 25.899 8.416 28.203 ;
     RECT  3.968 26.731 4 28.917 ;
     RECT  6.208 27.893 6.24 29.163 ;
     RECT  8.384 28.203 8.416 30.379 ;
     RECT  3.968 28.917 4.576 30.507 ;
     RECT  4.544 30.507 4.576 30.827 ;
  END
END ot_hdc_v41_fh_sram_lane_hardened
END LIBRARY
